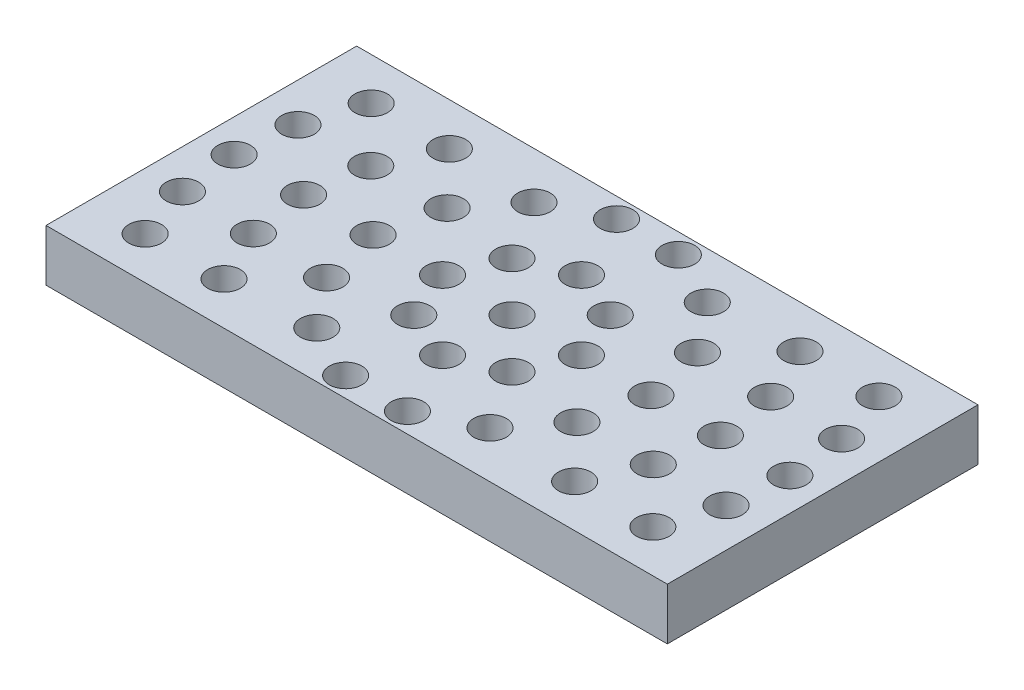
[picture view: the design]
ISO-10303-21;
HEADER;
FILE_DESCRIPTION(('STEP AP214'),'2;1');
FILE_NAME('part.step','',(''),(''),'','','');
FILE_SCHEMA(('AUTOMOTIVE_DESIGN { 1 0 10303 214 1 1 1 1 }'));
ENDSEC;
DATA;
#1=APPLICATION_CONTEXT('core data for automotive mechanical design processes');
#2=APPLICATION_PROTOCOL_DEFINITION('international standard','automotive_design',2000,#1);
#3=PRODUCT_CONTEXT('',#1,'mechanical');
#4=PRODUCT('Part','Part','',(#3));
#5=PRODUCT_RELATED_PRODUCT_CATEGORY('part','',(#4));
#6=PRODUCT_DEFINITION_FORMATION('','',#4);
#7=PRODUCT_DEFINITION_CONTEXT('part definition',#1,'design');
#8=PRODUCT_DEFINITION('design','',#6,#7);
#9=PRODUCT_DEFINITION_SHAPE('','',#8);
#10=(LENGTH_UNIT() NAMED_UNIT(*) SI_UNIT(.MILLI.,.METRE.));
#11=(NAMED_UNIT(*) PLANE_ANGLE_UNIT() SI_UNIT($,.RADIAN.));
#12=(NAMED_UNIT(*) SI_UNIT($,.STERADIAN.) SOLID_ANGLE_UNIT());
#13=UNCERTAINTY_MEASURE_WITH_UNIT(LENGTH_MEASURE(1.E-05),#10,'distance_accuracy_value','');
#14=(GEOMETRIC_REPRESENTATION_CONTEXT(3) GLOBAL_UNCERTAINTY_ASSIGNED_CONTEXT((#13)) GLOBAL_UNIT_ASSIGNED_CONTEXT((#10,
#11,#12)) REPRESENTATION_CONTEXT('',''));
#15=CARTESIAN_POINT('',(0.,0.,0.));
#16=DIRECTION('',(0.,0.,1.));
#17=DIRECTION('',(1.,0.,0.));
#18=AXIS2_PLACEMENT_3D('',#15,#16,#17);
#19=CARTESIAN_POINT('',(-76.2,12.7,-38.1));
#20=DIRECTION('',(1.,0.,0.));
#21=DIRECTION('',(0.,0.,-1.));
#22=AXIS2_PLACEMENT_3D('',#19,#20,#21);
#23=PLANE('',#22);
#24=DIRECTION('',(0.,0.,1.));
#25=VECTOR('',#24,1.);
#26=CARTESIAN_POINT('',(-76.2,0.,-38.1));
#27=LINE('',#26,#25);
#28=CARTESIAN_POINT('',(-76.2,0.,-38.1));
#29=VERTEX_POINT('',#28);
#30=CARTESIAN_POINT('',(-76.2,0.,38.1));
#31=VERTEX_POINT('',#30);
#32=EDGE_CURVE('E97',#29,#31,#27,.T.);
#33=ORIENTED_EDGE('',*,*,#32,.T.);
#34=DIRECTION('',(0.,-1.,0.));
#35=VECTOR('',#34,1.);
#36=CARTESIAN_POINT('',(-76.2,12.7,38.1));
#37=LINE('',#36,#35);
#38=CARTESIAN_POINT('',(-76.2,12.7,38.1));
#39=VERTEX_POINT('',#38);
#40=EDGE_CURVE('E12',#39,#31,#37,.T.);
#41=ORIENTED_EDGE('',*,*,#40,.F.);
#42=DIRECTION('',(0.,0.,1.));
#43=VECTOR('',#42,1.);
#44=CARTESIAN_POINT('',(-76.2,12.7,-38.1));
#45=LINE('',#44,#43);
#46=CARTESIAN_POINT('',(-76.2,12.7,-38.1));
#47=VERTEX_POINT('',#46);
#48=EDGE_CURVE('E85',#47,#39,#45,.T.);
#49=ORIENTED_EDGE('',*,*,#48,.F.);
#50=DIRECTION('',(0.,-1.,0.));
#51=VECTOR('',#50,1.);
#52=CARTESIAN_POINT('',(-76.2,12.7,-38.1));
#53=LINE('',#52,#51);
#54=EDGE_CURVE('E93',#47,#29,#53,.T.);
#55=ORIENTED_EDGE('',*,*,#54,.T.);
#56=EDGE_LOOP('',(#33,#41,#49,#55));
#57=FACE_BOUND('',#56,.T.);
#58=ADVANCED_FACE('F34',(#57),#23,.F.);
#59=CARTESIAN_POINT('',(-76.2,12.7,38.1));
#60=DIRECTION('',(0.,0.,-1.));
#61=DIRECTION('',(-1.,0.,0.));
#62=AXIS2_PLACEMENT_3D('',#59,#60,#61);
#63=PLANE('',#62);
#64=DIRECTION('',(1.,0.,0.));
#65=VECTOR('',#64,1.);
#66=CARTESIAN_POINT('',(-76.2,0.,38.1));
#67=LINE('',#66,#65);
#68=CARTESIAN_POINT('',(76.2,0.,38.1));
#69=VERTEX_POINT('',#68);
#70=EDGE_CURVE('E89',#31,#69,#67,.T.);
#71=ORIENTED_EDGE('',*,*,#70,.T.);
#72=DIRECTION('',(0.,-1.,0.));
#73=VECTOR('',#72,1.);
#74=CARTESIAN_POINT('',(76.2,12.7,38.1));
#75=LINE('',#74,#73);
#76=CARTESIAN_POINT('',(76.2,12.7,38.1));
#77=VERTEX_POINT('',#76);
#78=EDGE_CURVE('E42',#77,#69,#75,.T.);
#79=ORIENTED_EDGE('',*,*,#78,.F.);
#80=DIRECTION('',(1.,0.,0.));
#81=VECTOR('',#80,1.);
#82=CARTESIAN_POINT('',(-76.2,12.7,38.1));
#83=LINE('',#82,#81);
#84=EDGE_CURVE('E80',#39,#77,#83,.T.);
#85=ORIENTED_EDGE('',*,*,#84,.F.);
#86=ORIENTED_EDGE('',*,*,#40,.T.);
#87=EDGE_LOOP('',(#71,#79,#85,#86));
#88=FACE_BOUND('',#87,.T.);
#89=ADVANCED_FACE('F88',(#88),#63,.F.);
#90=CARTESIAN_POINT('',(76.2,12.7,-38.1));
#91=DIRECTION('',(-1.,0.,0.));
#92=DIRECTION('',(0.,0.,1.));
#93=AXIS2_PLACEMENT_3D('',#90,#91,#92);
#94=PLANE('',#93);
#95=DIRECTION('',(0.,0.,-1.));
#96=VECTOR('',#95,1.);
#97=CARTESIAN_POINT('',(76.2,0.,-38.1));
#98=LINE('',#97,#96);
#99=CARTESIAN_POINT('',(76.2,0.,-38.1));
#100=VERTEX_POINT('',#99);
#101=EDGE_CURVE('E67',#69,#100,#98,.T.);
#102=ORIENTED_EDGE('',*,*,#101,.T.);
#103=DIRECTION('',(0.,-1.,0.));
#104=VECTOR('',#103,1.);
#105=CARTESIAN_POINT('',(76.2,12.7,-38.1));
#106=LINE('',#105,#104);
#107=CARTESIAN_POINT('',(76.2,12.7,-38.1));
#108=VERTEX_POINT('',#107);
#109=EDGE_CURVE('E90',#108,#100,#106,.T.);
#110=ORIENTED_EDGE('',*,*,#109,.F.);
#111=DIRECTION('',(0.,0.,-1.));
#112=VECTOR('',#111,1.);
#113=CARTESIAN_POINT('',(76.2,12.7,-38.1));
#114=LINE('',#113,#112);
#115=EDGE_CURVE('E83',#77,#108,#114,.T.);
#116=ORIENTED_EDGE('',*,*,#115,.F.);
#117=ORIENTED_EDGE('',*,*,#78,.T.);
#118=EDGE_LOOP('',(#102,#110,#116,#117));
#119=FACE_BOUND('',#118,.T.);
#120=ADVANCED_FACE('F91',(#119),#94,.F.);
#121=CARTESIAN_POINT('',(-76.2,12.7,-38.1));
#122=DIRECTION('',(0.,0.,1.));
#123=DIRECTION('',(1.,0.,0.));
#124=AXIS2_PLACEMENT_3D('',#121,#122,#123);
#125=PLANE('',#124);
#126=DIRECTION('',(-1.,0.,0.));
#127=VECTOR('',#126,1.);
#128=CARTESIAN_POINT('',(-76.2,0.,-38.1));
#129=LINE('',#128,#127);
#130=EDGE_CURVE('E73',#100,#29,#129,.T.);
#131=ORIENTED_EDGE('',*,*,#130,.T.);
#132=ORIENTED_EDGE('',*,*,#54,.F.);
#133=DIRECTION('',(-1.,0.,0.));
#134=VECTOR('',#133,1.);
#135=CARTESIAN_POINT('',(-76.2,12.7,-38.1));
#136=LINE('',#135,#134);
#137=EDGE_CURVE('E50',#108,#47,#136,.T.);
#138=ORIENTED_EDGE('',*,*,#137,.F.);
#139=ORIENTED_EDGE('',*,*,#109,.T.);
#140=EDGE_LOOP('',(#131,#132,#138,#139));
#141=FACE_BOUND('',#140,.T.);
#142=ADVANCED_FACE('F105',(#141),#125,.F.);
#143=CARTESIAN_POINT('',(-76.2,12.7,38.1));
#144=DIRECTION('',(0.,1.,0.));
#145=DIRECTION('',(0.,0.,1.));
#146=AXIS2_PLACEMENT_3D('',#143,#144,#145);
#147=PLANE('',#146);
#148=CARTESIAN_POINT('',(66.6659939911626,12.7,-14.1702944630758));
#149=DIRECTION('',(0.,1.,0.));
#150=DIRECTION('',(1.,0.,0.));
#151=AXIS2_PLACEMENT_3D('',#148,#149,#150);
#152=CIRCLE('',#151,4.);
#153=CARTESIAN_POINT('',(70.6659939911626,12.7,-14.1702944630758));
#154=VERTEX_POINT('',#153);
#155=EDGE_CURVE('E363',#154,#154,#152,.T.);
#156=ORIENTED_EDGE('',*,*,#155,.F.);
#157=EDGE_LOOP('',(#156));
#158=FACE_BOUND('',#157,.T.);
#159=CARTESIAN_POINT('',(62.2630121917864,12.7,-27.7212790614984));
#160=DIRECTION('',(0.,1.,0.));
#161=DIRECTION('',(1.,0.,0.));
#162=AXIS2_PLACEMENT_3D('',#159,#160,#161);
#163=CIRCLE('',#162,4.);
#164=CARTESIAN_POINT('',(66.2630121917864,12.7,-27.7212790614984));
#165=VERTEX_POINT('',#164);
#166=EDGE_CURVE('E357',#165,#165,#163,.T.);
#167=ORIENTED_EDGE('',*,*,#166,.F.);
#168=EDGE_LOOP('',(#167));
#169=FACE_BOUND('',#168,.T.);
#170=CARTESIAN_POINT('',(49.0459359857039,12.7,-14.4011861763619));
#171=DIRECTION('',(0.,1.,0.));
#172=DIRECTION('',(1.,0.,0.));
#173=AXIS2_PLACEMENT_3D('',#170,#171,#172);
#174=CIRCLE('',#173,4.);
#175=CARTESIAN_POINT('',(53.0459359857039,12.7,-14.4011861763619));
#176=VERTEX_POINT('',#175);
#177=EDGE_CURVE('E351',#176,#176,#174,.T.);
#178=ORIENTED_EDGE('',*,*,#177,.F.);
#179=EDGE_LOOP('',(#178));
#180=FACE_BOUND('',#179,.T.);
#181=CARTESIAN_POINT('',(43.0019479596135,12.7,-27.6356738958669));
#182=DIRECTION('',(0.,1.,0.));
#183=DIRECTION('',(1.,0.,0.));
#184=AXIS2_PLACEMENT_3D('',#181,#182,#183);
#185=CIRCLE('',#184,4.);
#186=CARTESIAN_POINT('',(47.0019479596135,12.7,-27.6356738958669));
#187=VERTEX_POINT('',#186);
#188=EDGE_CURVE('E345',#187,#187,#185,.T.);
#189=ORIENTED_EDGE('',*,*,#188,.F.);
#190=EDGE_LOOP('',(#189));
#191=FACE_BOUND('',#190,.T.);
#192=CARTESIAN_POINT('',(-62.2630121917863,12.7,-27.7212790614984));
#193=DIRECTION('',(0.,1.,0.));
#194=DIRECTION('',(1.,0.,0.));
#195=AXIS2_PLACEMENT_3D('',#192,#193,#194);
#196=CIRCLE('',#195,4.);
#197=CARTESIAN_POINT('',(-58.2630121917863,12.7,-27.7212790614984));
#198=VERTEX_POINT('',#197);
#199=EDGE_CURVE('E339',#198,#198,#196,.T.);
#200=ORIENTED_EDGE('',*,*,#199,.F.);
#201=EDGE_LOOP('',(#200));
#202=FACE_BOUND('',#201,.T.);
#203=CARTESIAN_POINT('',(-66.6659939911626,12.7,-14.1702944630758));
#204=DIRECTION('',(0.,1.,0.));
#205=DIRECTION('',(1.,0.,0.));
#206=AXIS2_PLACEMENT_3D('',#203,#204,#205);
#207=CIRCLE('',#206,4.);
#208=CARTESIAN_POINT('',(-62.6659939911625,12.7,-14.1702944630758));
#209=VERTEX_POINT('',#208);
#210=EDGE_CURVE('E333',#209,#209,#207,.T.);
#211=ORIENTED_EDGE('',*,*,#210,.F.);
#212=EDGE_LOOP('',(#211));
#213=FACE_BOUND('',#212,.T.);
#214=CARTESIAN_POINT('',(-68.1553519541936,12.7,0.));
#215=DIRECTION('',(0.,1.,0.));
#216=DIRECTION('',(1.,0.,0.));
#217=AXIS2_PLACEMENT_3D('',#214,#215,#216);
#218=CIRCLE('',#217,4.);
#219=CARTESIAN_POINT('',(-64.1553519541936,12.7,0.));
#220=VERTEX_POINT('',#219);
#221=EDGE_CURVE('E327',#220,#220,#218,.T.);
#222=ORIENTED_EDGE('',*,*,#221,.F.);
#223=EDGE_LOOP('',(#222));
#224=FACE_BOUND('',#223,.T.);
#225=CARTESIAN_POINT('',(-66.6659939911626,12.7,14.1702944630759));
#226=DIRECTION('',(0.,1.,0.));
#227=DIRECTION('',(1.,0.,0.));
#228=AXIS2_PLACEMENT_3D('',#225,#226,#227);
#229=CIRCLE('',#228,4.);
#230=CARTESIAN_POINT('',(-62.6659939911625,12.7,14.1702944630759));
#231=VERTEX_POINT('',#230);
#232=EDGE_CURVE('E321',#231,#231,#229,.T.);
#233=ORIENTED_EDGE('',*,*,#232,.F.);
#234=EDGE_LOOP('',(#233));
#235=FACE_BOUND('',#234,.T.);
#236=CARTESIAN_POINT('',(-62.2630121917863,12.7,27.7212790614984));
#237=DIRECTION('',(0.,1.,0.));
#238=DIRECTION('',(1.,0.,0.));
#239=AXIS2_PLACEMENT_3D('',#236,#237,#238);
#240=CIRCLE('',#239,4.);
#241=CARTESIAN_POINT('',(-58.2630121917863,12.7,27.7212790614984));
#242=VERTEX_POINT('',#241);
#243=EDGE_CURVE('E315',#242,#242,#240,.T.);
#244=ORIENTED_EDGE('',*,*,#243,.F.);
#245=EDGE_LOOP('',(#244));
#246=FACE_BOUND('',#245,.T.);
#247=CARTESIAN_POINT('',(-43.0019479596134,12.7,-27.6356738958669));
#248=DIRECTION('',(0.,1.,0.));
#249=DIRECTION('',(1.,0.,0.));
#250=AXIS2_PLACEMENT_3D('',#247,#248,#249);
#251=CIRCLE('',#250,4.);
#252=CARTESIAN_POINT('',(-39.0019479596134,12.7,-27.6356738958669));
#253=VERTEX_POINT('',#252);
#254=EDGE_CURVE('E309',#253,#253,#251,.T.);
#255=ORIENTED_EDGE('',*,*,#254,.F.);
#256=EDGE_LOOP('',(#255));
#257=FACE_BOUND('',#256,.T.);
#258=CARTESIAN_POINT('',(30.7029251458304,12.7,-14.7857494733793));
#259=DIRECTION('',(0.,1.,0.));
#260=DIRECTION('',(1.,0.,0.));
#261=AXIS2_PLACEMENT_3D('',#258,#259,#260);
#262=CIRCLE('',#261,4.);
#263=CARTESIAN_POINT('',(34.7029251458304,12.7,-14.7857494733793));
#264=VERTEX_POINT('',#263);
#265=EDGE_CURVE('E303',#264,#264,#262,.T.);
#266=ORIENTED_EDGE('',*,*,#265,.F.);
#267=EDGE_LOOP('',(#266));
#268=FACE_BOUND('',#267,.T.);
#269=CARTESIAN_POINT('',(-49.0459359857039,12.7,-14.4011861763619));
#270=DIRECTION('',(0.,1.,0.));
#271=DIRECTION('',(1.,0.,0.));
#272=AXIS2_PLACEMENT_3D('',#269,#270,#271);
#273=CIRCLE('',#272,4.);
#274=CARTESIAN_POINT('',(-45.0459359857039,12.7,-14.4011861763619));
#275=VERTEX_POINT('',#274);
#276=EDGE_CURVE('E297',#275,#275,#273,.T.);
#277=ORIENTED_EDGE('',*,*,#276,.F.);
#278=EDGE_LOOP('',(#277));
#279=FACE_BOUND('',#278,.T.);
#280=CARTESIAN_POINT('',(21.2470834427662,12.7,-26.6429999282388));
#281=DIRECTION('',(0.,1.,0.));
#282=DIRECTION('',(1.,0.,0.));
#283=AXIS2_PLACEMENT_3D('',#280,#281,#282);
#284=CIRCLE('',#283,4.);
#285=CARTESIAN_POINT('',(25.2470834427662,12.7,-26.6429999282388));
#286=VERTEX_POINT('',#285);
#287=EDGE_CURVE('E291',#286,#286,#284,.T.);
#288=ORIENTED_EDGE('',*,*,#287,.F.);
#289=EDGE_LOOP('',(#288));
#290=FACE_BOUND('',#289,.T.);
#291=CARTESIAN_POINT('',(-51.1165139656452,12.7,0.));
#292=DIRECTION('',(0.,1.,0.));
#293=DIRECTION('',(1.,0.,0.));
#294=AXIS2_PLACEMENT_3D('',#291,#292,#293);
#295=CIRCLE('',#294,4.);
#296=CARTESIAN_POINT('',(-47.1165139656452,12.7,0.));
#297=VERTEX_POINT('',#296);
#298=EDGE_CURVE('E285',#297,#297,#295,.T.);
#299=ORIENTED_EDGE('',*,*,#298,.F.);
#300=EDGE_LOOP('',(#299));
#301=FACE_BOUND('',#300,.T.);
#302=CARTESIAN_POINT('',(7.58299628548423,12.7,-33.2232774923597));
#303=DIRECTION('',(0.,1.,0.));
#304=DIRECTION('',(1.,0.,0.));
#305=AXIS2_PLACEMENT_3D('',#302,#303,#304);
#306=CIRCLE('',#305,4.);
#307=CARTESIAN_POINT('',(11.5829962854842,12.7,-33.2232774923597));
#308=VERTEX_POINT('',#307);
#309=EDGE_CURVE('E279',#308,#308,#306,.T.);
#310=ORIENTED_EDGE('',*,*,#309,.F.);
#311=EDGE_LOOP('',(#310));
#312=FACE_BOUND('',#311,.T.);
#313=CARTESIAN_POINT('',(-49.0459359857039,12.7,14.4011861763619));
#314=DIRECTION('',(0.,1.,0.));
#315=DIRECTION('',(1.,0.,0.));
#316=AXIS2_PLACEMENT_3D('',#313,#314,#315);
#317=CIRCLE('',#316,4.);
#318=CARTESIAN_POINT('',(-45.0459359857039,12.7,14.4011861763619));
#319=VERTEX_POINT('',#318);
#320=EDGE_CURVE('E273',#319,#319,#317,.T.);
#321=ORIENTED_EDGE('',*,*,#320,.F.);
#322=EDGE_LOOP('',(#321));
#323=FACE_BOUND('',#322,.T.);
#324=CARTESIAN_POINT('',(-7.58299628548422,12.7,-33.2232774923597));
#325=DIRECTION('',(0.,1.,0.));
#326=DIRECTION('',(1.,0.,0.));
#327=AXIS2_PLACEMENT_3D('',#324,#325,#326);
#328=CIRCLE('',#327,4.);
#329=CARTESIAN_POINT('',(-3.58299628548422,12.7,-33.2232774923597));
#330=VERTEX_POINT('',#329);
#331=EDGE_CURVE('E267',#330,#330,#328,.T.);
#332=ORIENTED_EDGE('',*,*,#331,.F.);
#333=EDGE_LOOP('',(#332));
#334=FACE_BOUND('',#333,.T.);
#335=CARTESIAN_POINT('',(-43.0019479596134,12.7,27.6356738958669));
#336=DIRECTION('',(0.,1.,0.));
#337=DIRECTION('',(1.,0.,0.));
#338=AXIS2_PLACEMENT_3D('',#335,#336,#337);
#339=CIRCLE('',#338,4.);
#340=CARTESIAN_POINT('',(-39.0019479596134,12.7,27.6356738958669));
#341=VERTEX_POINT('',#340);
#342=EDGE_CURVE('E261',#341,#341,#339,.T.);
#343=ORIENTED_EDGE('',*,*,#342,.F.);
#344=EDGE_LOOP('',(#343));
#345=FACE_BOUND('',#344,.T.);
#346=CARTESIAN_POINT('',(-21.2470834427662,12.7,-26.6429999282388));
#347=DIRECTION('',(0.,1.,0.));
#348=DIRECTION('',(1.,0.,0.));
#349=AXIS2_PLACEMENT_3D('',#346,#347,#348);
#350=CIRCLE('',#349,4.);
#351=CARTESIAN_POINT('',(-17.2470834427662,12.7,-26.6429999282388));
#352=VERTEX_POINT('',#351);
#353=EDGE_CURVE('E255',#352,#352,#350,.T.);
#354=ORIENTED_EDGE('',*,*,#353,.F.);
#355=EDGE_LOOP('',(#354));
#356=FACE_BOUND('',#355,.T.);
#357=CARTESIAN_POINT('',(-30.7029251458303,12.7,-14.7857494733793));
#358=DIRECTION('',(0.,1.,0.));
#359=DIRECTION('',(1.,0.,0.));
#360=AXIS2_PLACEMENT_3D('',#357,#358,#359);
#361=CIRCLE('',#360,4.);
#362=CARTESIAN_POINT('',(-26.7029251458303,12.7,-14.7857494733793));
#363=VERTEX_POINT('',#362);
#364=EDGE_CURVE('E249',#363,#363,#361,.T.);
#365=ORIENTED_EDGE('',*,*,#364,.F.);
#366=EDGE_LOOP('',(#365));
#367=FACE_BOUND('',#366,.T.);
#368=CARTESIAN_POINT('',(-34.0776759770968,12.7,0.));
#369=DIRECTION('',(0.,1.,0.));
#370=DIRECTION('',(1.,0.,0.));
#371=AXIS2_PLACEMENT_3D('',#368,#369,#370);
#372=CIRCLE('',#371,4.);
#373=CARTESIAN_POINT('',(-30.0776759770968,12.7,0.));
#374=VERTEX_POINT('',#373);
#375=EDGE_CURVE('E243',#374,#374,#372,.T.);
#376=ORIENTED_EDGE('',*,*,#375,.F.);
#377=EDGE_LOOP('',(#376));
#378=FACE_BOUND('',#377,.T.);
#379=CARTESIAN_POINT('',(12.0482778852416,12.7,-12.0482778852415));
#380=DIRECTION('',(0.,1.,0.));
#381=DIRECTION('',(1.,0.,0.));
#382=AXIS2_PLACEMENT_3D('',#379,#380,#381);
#383=CIRCLE('',#382,4.);
#384=CARTESIAN_POINT('',(16.0482778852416,12.7,-12.0482778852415));
#385=VERTEX_POINT('',#384);
#386=EDGE_CURVE('E237',#385,#385,#383,.T.);
#387=ORIENTED_EDGE('',*,*,#386,.F.);
#388=EDGE_LOOP('',(#387));
#389=FACE_BOUND('',#388,.T.);
#390=CARTESIAN_POINT('',(-30.7029251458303,12.7,14.7857494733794));
#391=DIRECTION('',(0.,1.,0.));
#392=DIRECTION('',(1.,0.,0.));
#393=AXIS2_PLACEMENT_3D('',#390,#391,#392);
#394=CIRCLE('',#393,4.);
#395=CARTESIAN_POINT('',(-26.7029251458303,12.7,14.7857494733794));
#396=VERTEX_POINT('',#395);
#397=EDGE_CURVE('E231',#396,#396,#394,.T.);
#398=ORIENTED_EDGE('',*,*,#397,.F.);
#399=EDGE_LOOP('',(#398));
#400=FACE_BOUND('',#399,.T.);
#401=CARTESIAN_POINT('',(0.,12.7,-17.0388379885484));
#402=DIRECTION('',(0.,1.,0.));
#403=DIRECTION('',(1.,0.,0.));
#404=AXIS2_PLACEMENT_3D('',#401,#402,#403);
#405=CIRCLE('',#404,4.);
#406=CARTESIAN_POINT('',(4.00000000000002,12.7,-17.0388379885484));
#407=VERTEX_POINT('',#406);
#408=EDGE_CURVE('E225',#407,#407,#405,.T.);
#409=ORIENTED_EDGE('',*,*,#408,.F.);
#410=EDGE_LOOP('',(#409));
#411=FACE_BOUND('',#410,.T.);
#412=CARTESIAN_POINT('',(-21.2470834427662,12.7,26.6429999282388));
#413=DIRECTION('',(0.,1.,0.));
#414=DIRECTION('',(1.,0.,0.));
#415=AXIS2_PLACEMENT_3D('',#412,#413,#414);
#416=CIRCLE('',#415,4.);
#417=CARTESIAN_POINT('',(-17.2470834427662,12.7,26.6429999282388));
#418=VERTEX_POINT('',#417);
#419=EDGE_CURVE('E219',#418,#418,#416,.T.);
#420=ORIENTED_EDGE('',*,*,#419,.F.);
#421=EDGE_LOOP('',(#420));
#422=FACE_BOUND('',#421,.T.);
#423=CARTESIAN_POINT('',(-12.0482778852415,12.7,-12.0482778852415));
#424=DIRECTION('',(0.,1.,0.));
#425=DIRECTION('',(1.,0.,0.));
#426=AXIS2_PLACEMENT_3D('',#423,#424,#425);
#427=CIRCLE('',#426,4.);
#428=CARTESIAN_POINT('',(-8.0482778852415,12.7,-12.0482778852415));
#429=VERTEX_POINT('',#428);
#430=EDGE_CURVE('E213',#429,#429,#427,.T.);
#431=ORIENTED_EDGE('',*,*,#430,.F.);
#432=EDGE_LOOP('',(#431));
#433=FACE_BOUND('',#432,.T.);
#434=CARTESIAN_POINT('',(-7.58299628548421,12.7,33.2232774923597));
#435=DIRECTION('',(0.,1.,0.));
#436=DIRECTION('',(1.,0.,0.));
#437=AXIS2_PLACEMENT_3D('',#434,#435,#436);
#438=CIRCLE('',#437,4.);
#439=CARTESIAN_POINT('',(-3.58299628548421,12.7,33.2232774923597));
#440=VERTEX_POINT('',#439);
#441=EDGE_CURVE('E207',#440,#440,#438,.T.);
#442=ORIENTED_EDGE('',*,*,#441,.F.);
#443=EDGE_LOOP('',(#442));
#444=FACE_BOUND('',#443,.T.);
#445=CARTESIAN_POINT('',(-17.0388379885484,12.7,0.));
#446=DIRECTION('',(0.,1.,0.));
#447=DIRECTION('',(1.,0.,0.));
#448=AXIS2_PLACEMENT_3D('',#445,#446,#447);
#449=CIRCLE('',#448,4.);
#450=CARTESIAN_POINT('',(-13.0388379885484,12.7,0.));
#451=VERTEX_POINT('',#450);
#452=EDGE_CURVE('E201',#451,#451,#449,.T.);
#453=ORIENTED_EDGE('',*,*,#452,.F.);
#454=EDGE_LOOP('',(#453));
#455=FACE_BOUND('',#454,.T.);
#456=CARTESIAN_POINT('',(7.58299628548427,12.7,33.2232774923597));
#457=DIRECTION('',(0.,1.,0.));
#458=DIRECTION('',(1.,0.,0.));
#459=AXIS2_PLACEMENT_3D('',#456,#457,#458);
#460=CIRCLE('',#459,4.);
#461=CARTESIAN_POINT('',(11.5829962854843,12.7,33.2232774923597));
#462=VERTEX_POINT('',#461);
#463=EDGE_CURVE('E195',#462,#462,#460,.T.);
#464=ORIENTED_EDGE('',*,*,#463,.F.);
#465=EDGE_LOOP('',(#464));
#466=FACE_BOUND('',#465,.T.);
#467=CARTESIAN_POINT('',(-12.0482778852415,12.7,12.0482778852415));
#468=DIRECTION('',(0.,1.,0.));
#469=DIRECTION('',(1.,0.,0.));
#470=AXIS2_PLACEMENT_3D('',#467,#468,#469);
#471=CIRCLE('',#470,4.);
#472=CARTESIAN_POINT('',(-8.0482778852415,12.7,12.0482778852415));
#473=VERTEX_POINT('',#472);
#474=EDGE_CURVE('E189',#473,#473,#471,.T.);
#475=ORIENTED_EDGE('',*,*,#474,.F.);
#476=EDGE_LOOP('',(#475));
#477=FACE_BOUND('',#476,.T.);
#478=CARTESIAN_POINT('',(62.2630121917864,12.7,27.7212790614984));
#479=DIRECTION('',(0.,1.,0.));
#480=DIRECTION('',(1.,0.,0.));
#481=AXIS2_PLACEMENT_3D('',#478,#479,#480);
#482=CIRCLE('',#481,4.);
#483=CARTESIAN_POINT('',(66.2630121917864,12.7,27.7212790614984));
#484=VERTEX_POINT('',#483);
#485=EDGE_CURVE('E183',#484,#484,#482,.T.);
#486=ORIENTED_EDGE('',*,*,#485,.F.);
#487=EDGE_LOOP('',(#486));
#488=FACE_BOUND('',#487,.T.);
#489=CARTESIAN_POINT('',(43.0019479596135,12.7,27.6356738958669));
#490=DIRECTION('',(0.,1.,0.));
#491=DIRECTION('',(1.,0.,0.));
#492=AXIS2_PLACEMENT_3D('',#489,#490,#491);
#493=CIRCLE('',#492,4.);
#494=CARTESIAN_POINT('',(47.0019479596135,12.7,27.6356738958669));
#495=VERTEX_POINT('',#494);
#496=EDGE_CURVE('E177',#495,#495,#493,.T.);
#497=ORIENTED_EDGE('',*,*,#496,.F.);
#498=EDGE_LOOP('',(#497));
#499=FACE_BOUND('',#498,.T.);
#500=CARTESIAN_POINT('',(21.2470834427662,12.7,26.6429999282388));
#501=DIRECTION('',(0.,1.,0.));
#502=DIRECTION('',(1.,0.,0.));
#503=AXIS2_PLACEMENT_3D('',#500,#501,#502);
#504=CIRCLE('',#503,4.);
#505=CARTESIAN_POINT('',(25.2470834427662,12.7,26.6429999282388));
#506=VERTEX_POINT('',#505);
#507=EDGE_CURVE('E171',#506,#506,#504,.T.);
#508=ORIENTED_EDGE('',*,*,#507,.F.);
#509=EDGE_LOOP('',(#508));
#510=FACE_BOUND('',#509,.T.);
#511=CARTESIAN_POINT('',(0.,12.7,17.0388379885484));
#512=DIRECTION('',(0.,1.,0.));
#513=DIRECTION('',(1.,0.,0.));
#514=AXIS2_PLACEMENT_3D('',#511,#512,#513);
#515=CIRCLE('',#514,4.);
#516=CARTESIAN_POINT('',(4.00000000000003,12.7,17.0388379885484));
#517=VERTEX_POINT('',#516);
#518=EDGE_CURVE('E165',#517,#517,#515,.T.);
#519=ORIENTED_EDGE('',*,*,#518,.F.);
#520=EDGE_LOOP('',(#519));
#521=FACE_BOUND('',#520,.T.);
#522=CARTESIAN_POINT('',(66.6659939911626,12.7,14.1702944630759));
#523=DIRECTION('',(0.,1.,0.));
#524=DIRECTION('',(1.,0.,0.));
#525=AXIS2_PLACEMENT_3D('',#522,#523,#524);
#526=CIRCLE('',#525,4.);
#527=CARTESIAN_POINT('',(70.6659939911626,12.7,14.1702944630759));
#528=VERTEX_POINT('',#527);
#529=EDGE_CURVE('E159',#528,#528,#526,.T.);
#530=ORIENTED_EDGE('',*,*,#529,.F.);
#531=EDGE_LOOP('',(#530));
#532=FACE_BOUND('',#531,.T.);
#533=CARTESIAN_POINT('',(49.0459359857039,12.7,14.4011861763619));
#534=DIRECTION('',(0.,1.,0.));
#535=DIRECTION('',(1.,0.,0.));
#536=AXIS2_PLACEMENT_3D('',#533,#534,#535);
#537=CIRCLE('',#536,4.);
#538=CARTESIAN_POINT('',(53.0459359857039,12.7,14.4011861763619));
#539=VERTEX_POINT('',#538);
#540=EDGE_CURVE('E153',#539,#539,#537,.T.);
#541=ORIENTED_EDGE('',*,*,#540,.F.);
#542=EDGE_LOOP('',(#541));
#543=FACE_BOUND('',#542,.T.);
#544=CARTESIAN_POINT('',(30.7029251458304,12.7,14.7857494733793));
#545=DIRECTION('',(0.,1.,0.));
#546=DIRECTION('',(1.,0.,0.));
#547=AXIS2_PLACEMENT_3D('',#544,#545,#546);
#548=CIRCLE('',#547,4.);
#549=CARTESIAN_POINT('',(34.7029251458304,12.7,14.7857494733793));
#550=VERTEX_POINT('',#549);
#551=EDGE_CURVE('E147',#550,#550,#548,.T.);
#552=ORIENTED_EDGE('',*,*,#551,.F.);
#553=EDGE_LOOP('',(#552));
#554=FACE_BOUND('',#553,.T.);
#555=CARTESIAN_POINT('',(12.0482778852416,12.7,12.0482778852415));
#556=DIRECTION('',(0.,1.,0.));
#557=DIRECTION('',(1.,0.,0.));
#558=AXIS2_PLACEMENT_3D('',#555,#556,#557);
#559=CIRCLE('',#558,4.);
#560=CARTESIAN_POINT('',(16.0482778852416,12.7,12.0482778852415));
#561=VERTEX_POINT('',#560);
#562=EDGE_CURVE('E141',#561,#561,#559,.T.);
#563=ORIENTED_EDGE('',*,*,#562,.F.);
#564=EDGE_LOOP('',(#563));
#565=FACE_BOUND('',#564,.T.);
#566=CARTESIAN_POINT('',(68.1553519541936,12.7,0.));
#567=DIRECTION('',(0.,1.,0.));
#568=DIRECTION('',(1.,0.,0.));
#569=AXIS2_PLACEMENT_3D('',#566,#567,#568);
#570=CIRCLE('',#569,4.);
#571=CARTESIAN_POINT('',(72.1553519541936,12.7,0.));
#572=VERTEX_POINT('',#571);
#573=EDGE_CURVE('E135',#572,#572,#570,.T.);
#574=ORIENTED_EDGE('',*,*,#573,.F.);
#575=EDGE_LOOP('',(#574));
#576=FACE_BOUND('',#575,.T.);
#577=CARTESIAN_POINT('',(51.1165139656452,12.7,0.));
#578=DIRECTION('',(0.,1.,0.));
#579=DIRECTION('',(1.,0.,0.));
#580=AXIS2_PLACEMENT_3D('',#577,#578,#579);
#581=CIRCLE('',#580,4.);
#582=CARTESIAN_POINT('',(55.1165139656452,12.7,0.));
#583=VERTEX_POINT('',#582);
#584=EDGE_CURVE('E129',#583,#583,#581,.T.);
#585=ORIENTED_EDGE('',*,*,#584,.F.);
#586=EDGE_LOOP('',(#585));
#587=FACE_BOUND('',#586,.T.);
#588=CARTESIAN_POINT('',(34.0776759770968,12.7,0.));
#589=DIRECTION('',(0.,1.,0.));
#590=DIRECTION('',(1.,0.,0.));
#591=AXIS2_PLACEMENT_3D('',#588,#589,#590);
#592=CIRCLE('',#591,4.);
#593=CARTESIAN_POINT('',(38.0776759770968,12.7,0.));
#594=VERTEX_POINT('',#593);
#595=EDGE_CURVE('E123',#594,#594,#592,.T.);
#596=ORIENTED_EDGE('',*,*,#595,.F.);
#597=EDGE_LOOP('',(#596));
#598=FACE_BOUND('',#597,.T.);
#599=CARTESIAN_POINT('',(17.0388379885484,12.7,0.));
#600=DIRECTION('',(0.,1.,0.));
#601=DIRECTION('',(1.,0.,0.));
#602=AXIS2_PLACEMENT_3D('',#599,#600,#601);
#603=CIRCLE('',#602,4.);
#604=CARTESIAN_POINT('',(21.0388379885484,12.7,0.));
#605=VERTEX_POINT('',#604);
#606=EDGE_CURVE('E117',#605,#605,#603,.T.);
#607=ORIENTED_EDGE('',*,*,#606,.F.);
#608=EDGE_LOOP('',(#607));
#609=FACE_BOUND('',#608,.T.);
#610=CARTESIAN_POINT('',(0.,12.7,0.));
#611=DIRECTION('',(0.,1.,0.));
#612=DIRECTION('',(1.,0.,0.));
#613=AXIS2_PLACEMENT_3D('',#610,#611,#612);
#614=CIRCLE('',#613,4.);
#615=CARTESIAN_POINT('',(4.00000000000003,12.7,0.));
#616=VERTEX_POINT('',#615);
#617=EDGE_CURVE('E111',#616,#616,#614,.T.);
#618=ORIENTED_EDGE('',*,*,#617,.F.);
#619=EDGE_LOOP('',(#618));
#620=FACE_BOUND('',#619,.T.);
#621=ORIENTED_EDGE('',*,*,#48,.T.);
#622=ORIENTED_EDGE('',*,*,#84,.T.);
#623=ORIENTED_EDGE('',*,*,#115,.T.);
#624=ORIENTED_EDGE('',*,*,#137,.T.);
#625=EDGE_LOOP('',(#621,#622,#623,#624));
#626=FACE_BOUND('',#625,.T.);
#627=ADVANCED_FACE('F81',(#158,#169,#180,#191,#202,#213,#224,#235,#246,#257,#268,#279,#290,#301,
#312,#323,#334,#345,#356,#367,#378,#389,#400,#411,#422,#433,#444,#455,#466,#477,#488,#499,#510,
#521,#532,#543,#554,#565,#576,#587,#598,#609,#620,#626),#147,.T.);
#628=CARTESIAN_POINT('',(-76.2,0.,38.1));
#629=DIRECTION('',(0.,1.,0.));
#630=DIRECTION('',(0.,0.,1.));
#631=AXIS2_PLACEMENT_3D('',#628,#629,#630);
#632=PLANE('',#631);
#633=CARTESIAN_POINT('',(66.6659939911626,0.,-14.1702944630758));
#634=DIRECTION('',(0.,1.,0.));
#635=DIRECTION('',(1.,0.,0.));
#636=AXIS2_PLACEMENT_3D('',#633,#634,#635);
#637=CIRCLE('',#636,4.);
#638=CARTESIAN_POINT('',(70.6659939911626,0.,-14.1702944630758));
#639=VERTEX_POINT('',#638);
#640=EDGE_CURVE('E360',#639,#639,#637,.T.);
#641=ORIENTED_EDGE('',*,*,#640,.T.);
#642=EDGE_LOOP('',(#641));
#643=FACE_BOUND('',#642,.T.);
#644=CARTESIAN_POINT('',(62.2630121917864,0.,-27.7212790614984));
#645=DIRECTION('',(0.,1.,0.));
#646=DIRECTION('',(1.,0.,0.));
#647=AXIS2_PLACEMENT_3D('',#644,#645,#646);
#648=CIRCLE('',#647,4.);
#649=CARTESIAN_POINT('',(66.2630121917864,0.,-27.7212790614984));
#650=VERTEX_POINT('',#649);
#651=EDGE_CURVE('E354',#650,#650,#648,.T.);
#652=ORIENTED_EDGE('',*,*,#651,.T.);
#653=EDGE_LOOP('',(#652));
#654=FACE_BOUND('',#653,.T.);
#655=CARTESIAN_POINT('',(49.0459359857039,0.,-14.4011861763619));
#656=DIRECTION('',(0.,1.,0.));
#657=DIRECTION('',(1.,0.,0.));
#658=AXIS2_PLACEMENT_3D('',#655,#656,#657);
#659=CIRCLE('',#658,4.);
#660=CARTESIAN_POINT('',(53.0459359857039,0.,-14.4011861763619));
#661=VERTEX_POINT('',#660);
#662=EDGE_CURVE('E348',#661,#661,#659,.T.);
#663=ORIENTED_EDGE('',*,*,#662,.T.);
#664=EDGE_LOOP('',(#663));
#665=FACE_BOUND('',#664,.T.);
#666=CARTESIAN_POINT('',(43.0019479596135,0.,-27.6356738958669));
#667=DIRECTION('',(0.,1.,0.));
#668=DIRECTION('',(1.,0.,0.));
#669=AXIS2_PLACEMENT_3D('',#666,#667,#668);
#670=CIRCLE('',#669,4.);
#671=CARTESIAN_POINT('',(47.0019479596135,0.,-27.6356738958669));
#672=VERTEX_POINT('',#671);
#673=EDGE_CURVE('E342',#672,#672,#670,.T.);
#674=ORIENTED_EDGE('',*,*,#673,.T.);
#675=EDGE_LOOP('',(#674));
#676=FACE_BOUND('',#675,.T.);
#677=CARTESIAN_POINT('',(-62.2630121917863,0.,-27.7212790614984));
#678=DIRECTION('',(0.,1.,0.));
#679=DIRECTION('',(1.,0.,0.));
#680=AXIS2_PLACEMENT_3D('',#677,#678,#679);
#681=CIRCLE('',#680,4.);
#682=CARTESIAN_POINT('',(-58.2630121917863,0.,-27.7212790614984));
#683=VERTEX_POINT('',#682);
#684=EDGE_CURVE('E336',#683,#683,#681,.T.);
#685=ORIENTED_EDGE('',*,*,#684,.T.);
#686=EDGE_LOOP('',(#685));
#687=FACE_BOUND('',#686,.T.);
#688=CARTESIAN_POINT('',(-66.6659939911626,0.,-14.1702944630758));
#689=DIRECTION('',(0.,1.,0.));
#690=DIRECTION('',(1.,0.,0.));
#691=AXIS2_PLACEMENT_3D('',#688,#689,#690);
#692=CIRCLE('',#691,4.);
#693=CARTESIAN_POINT('',(-62.6659939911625,0.,-14.1702944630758));
#694=VERTEX_POINT('',#693);
#695=EDGE_CURVE('E330',#694,#694,#692,.T.);
#696=ORIENTED_EDGE('',*,*,#695,.T.);
#697=EDGE_LOOP('',(#696));
#698=FACE_BOUND('',#697,.T.);
#699=CARTESIAN_POINT('',(-68.1553519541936,0.,0.));
#700=DIRECTION('',(0.,1.,0.));
#701=DIRECTION('',(1.,0.,0.));
#702=AXIS2_PLACEMENT_3D('',#699,#700,#701);
#703=CIRCLE('',#702,4.);
#704=CARTESIAN_POINT('',(-64.1553519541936,0.,0.));
#705=VERTEX_POINT('',#704);
#706=EDGE_CURVE('E324',#705,#705,#703,.T.);
#707=ORIENTED_EDGE('',*,*,#706,.T.);
#708=EDGE_LOOP('',(#707));
#709=FACE_BOUND('',#708,.T.);
#710=CARTESIAN_POINT('',(-66.6659939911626,0.,14.1702944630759));
#711=DIRECTION('',(0.,1.,0.));
#712=DIRECTION('',(1.,0.,0.));
#713=AXIS2_PLACEMENT_3D('',#710,#711,#712);
#714=CIRCLE('',#713,4.);
#715=CARTESIAN_POINT('',(-62.6659939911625,0.,14.1702944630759));
#716=VERTEX_POINT('',#715);
#717=EDGE_CURVE('E318',#716,#716,#714,.T.);
#718=ORIENTED_EDGE('',*,*,#717,.T.);
#719=EDGE_LOOP('',(#718));
#720=FACE_BOUND('',#719,.T.);
#721=CARTESIAN_POINT('',(-62.2630121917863,0.,27.7212790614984));
#722=DIRECTION('',(0.,1.,0.));
#723=DIRECTION('',(1.,0.,0.));
#724=AXIS2_PLACEMENT_3D('',#721,#722,#723);
#725=CIRCLE('',#724,4.);
#726=CARTESIAN_POINT('',(-58.2630121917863,0.,27.7212790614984));
#727=VERTEX_POINT('',#726);
#728=EDGE_CURVE('E312',#727,#727,#725,.T.);
#729=ORIENTED_EDGE('',*,*,#728,.T.);
#730=EDGE_LOOP('',(#729));
#731=FACE_BOUND('',#730,.T.);
#732=CARTESIAN_POINT('',(-43.0019479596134,0.,-27.6356738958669));
#733=DIRECTION('',(0.,1.,0.));
#734=DIRECTION('',(1.,0.,0.));
#735=AXIS2_PLACEMENT_3D('',#732,#733,#734);
#736=CIRCLE('',#735,4.);
#737=CARTESIAN_POINT('',(-39.0019479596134,0.,-27.6356738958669));
#738=VERTEX_POINT('',#737);
#739=EDGE_CURVE('E306',#738,#738,#736,.T.);
#740=ORIENTED_EDGE('',*,*,#739,.T.);
#741=EDGE_LOOP('',(#740));
#742=FACE_BOUND('',#741,.T.);
#743=CARTESIAN_POINT('',(30.7029251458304,0.,-14.7857494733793));
#744=DIRECTION('',(0.,1.,0.));
#745=DIRECTION('',(1.,0.,0.));
#746=AXIS2_PLACEMENT_3D('',#743,#744,#745);
#747=CIRCLE('',#746,4.);
#748=CARTESIAN_POINT('',(34.7029251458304,0.,-14.7857494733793));
#749=VERTEX_POINT('',#748);
#750=EDGE_CURVE('E300',#749,#749,#747,.T.);
#751=ORIENTED_EDGE('',*,*,#750,.T.);
#752=EDGE_LOOP('',(#751));
#753=FACE_BOUND('',#752,.T.);
#754=CARTESIAN_POINT('',(-49.0459359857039,0.,-14.4011861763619));
#755=DIRECTION('',(0.,1.,0.));
#756=DIRECTION('',(1.,0.,0.));
#757=AXIS2_PLACEMENT_3D('',#754,#755,#756);
#758=CIRCLE('',#757,4.);
#759=CARTESIAN_POINT('',(-45.0459359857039,0.,-14.4011861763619));
#760=VERTEX_POINT('',#759);
#761=EDGE_CURVE('E294',#760,#760,#758,.T.);
#762=ORIENTED_EDGE('',*,*,#761,.T.);
#763=EDGE_LOOP('',(#762));
#764=FACE_BOUND('',#763,.T.);
#765=CARTESIAN_POINT('',(21.2470834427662,0.,-26.6429999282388));
#766=DIRECTION('',(0.,1.,0.));
#767=DIRECTION('',(1.,0.,0.));
#768=AXIS2_PLACEMENT_3D('',#765,#766,#767);
#769=CIRCLE('',#768,4.);
#770=CARTESIAN_POINT('',(25.2470834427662,0.,-26.6429999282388));
#771=VERTEX_POINT('',#770);
#772=EDGE_CURVE('E288',#771,#771,#769,.T.);
#773=ORIENTED_EDGE('',*,*,#772,.T.);
#774=EDGE_LOOP('',(#773));
#775=FACE_BOUND('',#774,.T.);
#776=CARTESIAN_POINT('',(-51.1165139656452,0.,0.));
#777=DIRECTION('',(0.,1.,0.));
#778=DIRECTION('',(1.,0.,0.));
#779=AXIS2_PLACEMENT_3D('',#776,#777,#778);
#780=CIRCLE('',#779,4.);
#781=CARTESIAN_POINT('',(-47.1165139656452,0.,0.));
#782=VERTEX_POINT('',#781);
#783=EDGE_CURVE('E282',#782,#782,#780,.T.);
#784=ORIENTED_EDGE('',*,*,#783,.T.);
#785=EDGE_LOOP('',(#784));
#786=FACE_BOUND('',#785,.T.);
#787=CARTESIAN_POINT('',(7.58299628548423,0.,-33.2232774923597));
#788=DIRECTION('',(0.,1.,0.));
#789=DIRECTION('',(1.,0.,0.));
#790=AXIS2_PLACEMENT_3D('',#787,#788,#789);
#791=CIRCLE('',#790,4.);
#792=CARTESIAN_POINT('',(11.5829962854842,0.,-33.2232774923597));
#793=VERTEX_POINT('',#792);
#794=EDGE_CURVE('E276',#793,#793,#791,.T.);
#795=ORIENTED_EDGE('',*,*,#794,.T.);
#796=EDGE_LOOP('',(#795));
#797=FACE_BOUND('',#796,.T.);
#798=CARTESIAN_POINT('',(-49.0459359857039,0.,14.4011861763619));
#799=DIRECTION('',(0.,1.,0.));
#800=DIRECTION('',(1.,0.,0.));
#801=AXIS2_PLACEMENT_3D('',#798,#799,#800);
#802=CIRCLE('',#801,4.);
#803=CARTESIAN_POINT('',(-45.0459359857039,0.,14.4011861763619));
#804=VERTEX_POINT('',#803);
#805=EDGE_CURVE('E270',#804,#804,#802,.T.);
#806=ORIENTED_EDGE('',*,*,#805,.T.);
#807=EDGE_LOOP('',(#806));
#808=FACE_BOUND('',#807,.T.);
#809=CARTESIAN_POINT('',(-7.58299628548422,0.,-33.2232774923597));
#810=DIRECTION('',(0.,1.,0.));
#811=DIRECTION('',(1.,0.,0.));
#812=AXIS2_PLACEMENT_3D('',#809,#810,#811);
#813=CIRCLE('',#812,4.);
#814=CARTESIAN_POINT('',(-3.58299628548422,0.,-33.2232774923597));
#815=VERTEX_POINT('',#814);
#816=EDGE_CURVE('E264',#815,#815,#813,.T.);
#817=ORIENTED_EDGE('',*,*,#816,.T.);
#818=EDGE_LOOP('',(#817));
#819=FACE_BOUND('',#818,.T.);
#820=CARTESIAN_POINT('',(-43.0019479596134,0.,27.6356738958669));
#821=DIRECTION('',(0.,1.,0.));
#822=DIRECTION('',(1.,0.,0.));
#823=AXIS2_PLACEMENT_3D('',#820,#821,#822);
#824=CIRCLE('',#823,4.);
#825=CARTESIAN_POINT('',(-39.0019479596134,0.,27.6356738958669));
#826=VERTEX_POINT('',#825);
#827=EDGE_CURVE('E258',#826,#826,#824,.T.);
#828=ORIENTED_EDGE('',*,*,#827,.T.);
#829=EDGE_LOOP('',(#828));
#830=FACE_BOUND('',#829,.T.);
#831=CARTESIAN_POINT('',(-21.2470834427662,0.,-26.6429999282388));
#832=DIRECTION('',(0.,1.,0.));
#833=DIRECTION('',(1.,0.,0.));
#834=AXIS2_PLACEMENT_3D('',#831,#832,#833);
#835=CIRCLE('',#834,4.);
#836=CARTESIAN_POINT('',(-17.2470834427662,0.,-26.6429999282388));
#837=VERTEX_POINT('',#836);
#838=EDGE_CURVE('E252',#837,#837,#835,.T.);
#839=ORIENTED_EDGE('',*,*,#838,.T.);
#840=EDGE_LOOP('',(#839));
#841=FACE_BOUND('',#840,.T.);
#842=CARTESIAN_POINT('',(-30.7029251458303,0.,-14.7857494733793));
#843=DIRECTION('',(0.,1.,0.));
#844=DIRECTION('',(1.,0.,0.));
#845=AXIS2_PLACEMENT_3D('',#842,#843,#844);
#846=CIRCLE('',#845,4.);
#847=CARTESIAN_POINT('',(-26.7029251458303,0.,-14.7857494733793));
#848=VERTEX_POINT('',#847);
#849=EDGE_CURVE('E246',#848,#848,#846,.T.);
#850=ORIENTED_EDGE('',*,*,#849,.T.);
#851=EDGE_LOOP('',(#850));
#852=FACE_BOUND('',#851,.T.);
#853=CARTESIAN_POINT('',(-34.0776759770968,0.,0.));
#854=DIRECTION('',(0.,1.,0.));
#855=DIRECTION('',(1.,0.,0.));
#856=AXIS2_PLACEMENT_3D('',#853,#854,#855);
#857=CIRCLE('',#856,4.);
#858=CARTESIAN_POINT('',(-30.0776759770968,0.,0.));
#859=VERTEX_POINT('',#858);
#860=EDGE_CURVE('E240',#859,#859,#857,.T.);
#861=ORIENTED_EDGE('',*,*,#860,.T.);
#862=EDGE_LOOP('',(#861));
#863=FACE_BOUND('',#862,.T.);
#864=CARTESIAN_POINT('',(12.0482778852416,0.,-12.0482778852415));
#865=DIRECTION('',(0.,1.,0.));
#866=DIRECTION('',(1.,0.,0.));
#867=AXIS2_PLACEMENT_3D('',#864,#865,#866);
#868=CIRCLE('',#867,4.);
#869=CARTESIAN_POINT('',(16.0482778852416,0.,-12.0482778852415));
#870=VERTEX_POINT('',#869);
#871=EDGE_CURVE('E234',#870,#870,#868,.T.);
#872=ORIENTED_EDGE('',*,*,#871,.T.);
#873=EDGE_LOOP('',(#872));
#874=FACE_BOUND('',#873,.T.);
#875=CARTESIAN_POINT('',(-30.7029251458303,0.,14.7857494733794));
#876=DIRECTION('',(0.,1.,0.));
#877=DIRECTION('',(1.,0.,0.));
#878=AXIS2_PLACEMENT_3D('',#875,#876,#877);
#879=CIRCLE('',#878,4.);
#880=CARTESIAN_POINT('',(-26.7029251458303,0.,14.7857494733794));
#881=VERTEX_POINT('',#880);
#882=EDGE_CURVE('E228',#881,#881,#879,.T.);
#883=ORIENTED_EDGE('',*,*,#882,.T.);
#884=EDGE_LOOP('',(#883));
#885=FACE_BOUND('',#884,.T.);
#886=CARTESIAN_POINT('',(0.,0.,-17.0388379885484));
#887=DIRECTION('',(0.,1.,0.));
#888=DIRECTION('',(1.,0.,0.));
#889=AXIS2_PLACEMENT_3D('',#886,#887,#888);
#890=CIRCLE('',#889,4.);
#891=CARTESIAN_POINT('',(4.00000000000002,0.,-17.0388379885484));
#892=VERTEX_POINT('',#891);
#893=EDGE_CURVE('E222',#892,#892,#890,.T.);
#894=ORIENTED_EDGE('',*,*,#893,.T.);
#895=EDGE_LOOP('',(#894));
#896=FACE_BOUND('',#895,.T.);
#897=CARTESIAN_POINT('',(-21.2470834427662,0.,26.6429999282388));
#898=DIRECTION('',(0.,1.,0.));
#899=DIRECTION('',(1.,0.,0.));
#900=AXIS2_PLACEMENT_3D('',#897,#898,#899);
#901=CIRCLE('',#900,4.);
#902=CARTESIAN_POINT('',(-17.2470834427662,0.,26.6429999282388));
#903=VERTEX_POINT('',#902);
#904=EDGE_CURVE('E216',#903,#903,#901,.T.);
#905=ORIENTED_EDGE('',*,*,#904,.T.);
#906=EDGE_LOOP('',(#905));
#907=FACE_BOUND('',#906,.T.);
#908=CARTESIAN_POINT('',(-12.0482778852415,0.,-12.0482778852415));
#909=DIRECTION('',(0.,1.,0.));
#910=DIRECTION('',(1.,0.,0.));
#911=AXIS2_PLACEMENT_3D('',#908,#909,#910);
#912=CIRCLE('',#911,4.);
#913=CARTESIAN_POINT('',(-8.0482778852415,0.,-12.0482778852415));
#914=VERTEX_POINT('',#913);
#915=EDGE_CURVE('E210',#914,#914,#912,.T.);
#916=ORIENTED_EDGE('',*,*,#915,.T.);
#917=EDGE_LOOP('',(#916));
#918=FACE_BOUND('',#917,.T.);
#919=CARTESIAN_POINT('',(-7.58299628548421,0.,33.2232774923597));
#920=DIRECTION('',(0.,1.,0.));
#921=DIRECTION('',(1.,0.,0.));
#922=AXIS2_PLACEMENT_3D('',#919,#920,#921);
#923=CIRCLE('',#922,4.);
#924=CARTESIAN_POINT('',(-3.58299628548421,0.,33.2232774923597));
#925=VERTEX_POINT('',#924);
#926=EDGE_CURVE('E204',#925,#925,#923,.T.);
#927=ORIENTED_EDGE('',*,*,#926,.T.);
#928=EDGE_LOOP('',(#927));
#929=FACE_BOUND('',#928,.T.);
#930=CARTESIAN_POINT('',(-17.0388379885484,0.,0.));
#931=DIRECTION('',(0.,1.,0.));
#932=DIRECTION('',(1.,0.,0.));
#933=AXIS2_PLACEMENT_3D('',#930,#931,#932);
#934=CIRCLE('',#933,4.);
#935=CARTESIAN_POINT('',(-13.0388379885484,0.,0.));
#936=VERTEX_POINT('',#935);
#937=EDGE_CURVE('E198',#936,#936,#934,.T.);
#938=ORIENTED_EDGE('',*,*,#937,.T.);
#939=EDGE_LOOP('',(#938));
#940=FACE_BOUND('',#939,.T.);
#941=CARTESIAN_POINT('',(7.58299628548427,0.,33.2232774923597));
#942=DIRECTION('',(0.,1.,0.));
#943=DIRECTION('',(1.,0.,0.));
#944=AXIS2_PLACEMENT_3D('',#941,#942,#943);
#945=CIRCLE('',#944,4.);
#946=CARTESIAN_POINT('',(11.5829962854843,0.,33.2232774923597));
#947=VERTEX_POINT('',#946);
#948=EDGE_CURVE('E192',#947,#947,#945,.T.);
#949=ORIENTED_EDGE('',*,*,#948,.T.);
#950=EDGE_LOOP('',(#949));
#951=FACE_BOUND('',#950,.T.);
#952=CARTESIAN_POINT('',(-12.0482778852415,0.,12.0482778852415));
#953=DIRECTION('',(0.,1.,0.));
#954=DIRECTION('',(1.,0.,0.));
#955=AXIS2_PLACEMENT_3D('',#952,#953,#954);
#956=CIRCLE('',#955,4.);
#957=CARTESIAN_POINT('',(-8.0482778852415,0.,12.0482778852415));
#958=VERTEX_POINT('',#957);
#959=EDGE_CURVE('E186',#958,#958,#956,.T.);
#960=ORIENTED_EDGE('',*,*,#959,.T.);
#961=EDGE_LOOP('',(#960));
#962=FACE_BOUND('',#961,.T.);
#963=CARTESIAN_POINT('',(62.2630121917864,0.,27.7212790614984));
#964=DIRECTION('',(0.,1.,0.));
#965=DIRECTION('',(1.,0.,0.));
#966=AXIS2_PLACEMENT_3D('',#963,#964,#965);
#967=CIRCLE('',#966,4.);
#968=CARTESIAN_POINT('',(66.2630121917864,0.,27.7212790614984));
#969=VERTEX_POINT('',#968);
#970=EDGE_CURVE('E180',#969,#969,#967,.T.);
#971=ORIENTED_EDGE('',*,*,#970,.T.);
#972=EDGE_LOOP('',(#971));
#973=FACE_BOUND('',#972,.T.);
#974=CARTESIAN_POINT('',(43.0019479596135,0.,27.6356738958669));
#975=DIRECTION('',(0.,1.,0.));
#976=DIRECTION('',(1.,0.,0.));
#977=AXIS2_PLACEMENT_3D('',#974,#975,#976);
#978=CIRCLE('',#977,4.);
#979=CARTESIAN_POINT('',(47.0019479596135,0.,27.6356738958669));
#980=VERTEX_POINT('',#979);
#981=EDGE_CURVE('E174',#980,#980,#978,.T.);
#982=ORIENTED_EDGE('',*,*,#981,.T.);
#983=EDGE_LOOP('',(#982));
#984=FACE_BOUND('',#983,.T.);
#985=CARTESIAN_POINT('',(21.2470834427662,0.,26.6429999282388));
#986=DIRECTION('',(0.,1.,0.));
#987=DIRECTION('',(1.,0.,0.));
#988=AXIS2_PLACEMENT_3D('',#985,#986,#987);
#989=CIRCLE('',#988,4.);
#990=CARTESIAN_POINT('',(25.2470834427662,0.,26.6429999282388));
#991=VERTEX_POINT('',#990);
#992=EDGE_CURVE('E168',#991,#991,#989,.T.);
#993=ORIENTED_EDGE('',*,*,#992,.T.);
#994=EDGE_LOOP('',(#993));
#995=FACE_BOUND('',#994,.T.);
#996=CARTESIAN_POINT('',(0.,0.,17.0388379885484));
#997=DIRECTION('',(0.,1.,0.));
#998=DIRECTION('',(1.,0.,0.));
#999=AXIS2_PLACEMENT_3D('',#996,#997,#998);
#1000=CIRCLE('',#999,4.);
#1001=CARTESIAN_POINT('',(4.00000000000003,0.,17.0388379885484));
#1002=VERTEX_POINT('',#1001);
#1003=EDGE_CURVE('E162',#1002,#1002,#1000,.T.);
#1004=ORIENTED_EDGE('',*,*,#1003,.T.);
#1005=EDGE_LOOP('',(#1004));
#1006=FACE_BOUND('',#1005,.T.);
#1007=CARTESIAN_POINT('',(66.6659939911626,0.,14.1702944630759));
#1008=DIRECTION('',(0.,1.,0.));
#1009=DIRECTION('',(1.,0.,0.));
#1010=AXIS2_PLACEMENT_3D('',#1007,#1008,#1009);
#1011=CIRCLE('',#1010,4.);
#1012=CARTESIAN_POINT('',(70.6659939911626,0.,14.1702944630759));
#1013=VERTEX_POINT('',#1012);
#1014=EDGE_CURVE('E156',#1013,#1013,#1011,.T.);
#1015=ORIENTED_EDGE('',*,*,#1014,.T.);
#1016=EDGE_LOOP('',(#1015));
#1017=FACE_BOUND('',#1016,.T.);
#1018=CARTESIAN_POINT('',(49.0459359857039,0.,14.4011861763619));
#1019=DIRECTION('',(0.,1.,0.));
#1020=DIRECTION('',(1.,0.,0.));
#1021=AXIS2_PLACEMENT_3D('',#1018,#1019,#1020);
#1022=CIRCLE('',#1021,4.);
#1023=CARTESIAN_POINT('',(53.0459359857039,0.,14.4011861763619));
#1024=VERTEX_POINT('',#1023);
#1025=EDGE_CURVE('E150',#1024,#1024,#1022,.T.);
#1026=ORIENTED_EDGE('',*,*,#1025,.T.);
#1027=EDGE_LOOP('',(#1026));
#1028=FACE_BOUND('',#1027,.T.);
#1029=CARTESIAN_POINT('',(30.7029251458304,0.,14.7857494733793));
#1030=DIRECTION('',(0.,1.,0.));
#1031=DIRECTION('',(1.,0.,0.));
#1032=AXIS2_PLACEMENT_3D('',#1029,#1030,#1031);
#1033=CIRCLE('',#1032,4.);
#1034=CARTESIAN_POINT('',(34.7029251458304,0.,14.7857494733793));
#1035=VERTEX_POINT('',#1034);
#1036=EDGE_CURVE('E144',#1035,#1035,#1033,.T.);
#1037=ORIENTED_EDGE('',*,*,#1036,.T.);
#1038=EDGE_LOOP('',(#1037));
#1039=FACE_BOUND('',#1038,.T.);
#1040=CARTESIAN_POINT('',(12.0482778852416,0.,12.0482778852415));
#1041=DIRECTION('',(0.,1.,0.));
#1042=DIRECTION('',(1.,0.,0.));
#1043=AXIS2_PLACEMENT_3D('',#1040,#1041,#1042);
#1044=CIRCLE('',#1043,4.);
#1045=CARTESIAN_POINT('',(16.0482778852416,0.,12.0482778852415));
#1046=VERTEX_POINT('',#1045);
#1047=EDGE_CURVE('E138',#1046,#1046,#1044,.T.);
#1048=ORIENTED_EDGE('',*,*,#1047,.T.);
#1049=EDGE_LOOP('',(#1048));
#1050=FACE_BOUND('',#1049,.T.);
#1051=CARTESIAN_POINT('',(68.1553519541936,0.,0.));
#1052=DIRECTION('',(0.,1.,0.));
#1053=DIRECTION('',(1.,0.,0.));
#1054=AXIS2_PLACEMENT_3D('',#1051,#1052,#1053);
#1055=CIRCLE('',#1054,4.);
#1056=CARTESIAN_POINT('',(72.1553519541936,0.,0.));
#1057=VERTEX_POINT('',#1056);
#1058=EDGE_CURVE('E132',#1057,#1057,#1055,.T.);
#1059=ORIENTED_EDGE('',*,*,#1058,.T.);
#1060=EDGE_LOOP('',(#1059));
#1061=FACE_BOUND('',#1060,.T.);
#1062=CARTESIAN_POINT('',(51.1165139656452,0.,0.));
#1063=DIRECTION('',(0.,1.,0.));
#1064=DIRECTION('',(1.,0.,0.));
#1065=AXIS2_PLACEMENT_3D('',#1062,#1063,#1064);
#1066=CIRCLE('',#1065,4.);
#1067=CARTESIAN_POINT('',(55.1165139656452,0.,0.));
#1068=VERTEX_POINT('',#1067);
#1069=EDGE_CURVE('E126',#1068,#1068,#1066,.T.);
#1070=ORIENTED_EDGE('',*,*,#1069,.T.);
#1071=EDGE_LOOP('',(#1070));
#1072=FACE_BOUND('',#1071,.T.);
#1073=CARTESIAN_POINT('',(34.0776759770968,0.,0.));
#1074=DIRECTION('',(0.,1.,0.));
#1075=DIRECTION('',(1.,0.,0.));
#1076=AXIS2_PLACEMENT_3D('',#1073,#1074,#1075);
#1077=CIRCLE('',#1076,4.);
#1078=CARTESIAN_POINT('',(38.0776759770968,0.,0.));
#1079=VERTEX_POINT('',#1078);
#1080=EDGE_CURVE('E120',#1079,#1079,#1077,.T.);
#1081=ORIENTED_EDGE('',*,*,#1080,.T.);
#1082=EDGE_LOOP('',(#1081));
#1083=FACE_BOUND('',#1082,.T.);
#1084=CARTESIAN_POINT('',(17.0388379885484,0.,0.));
#1085=DIRECTION('',(0.,1.,0.));
#1086=DIRECTION('',(1.,0.,0.));
#1087=AXIS2_PLACEMENT_3D('',#1084,#1085,#1086);
#1088=CIRCLE('',#1087,4.);
#1089=CARTESIAN_POINT('',(21.0388379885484,0.,0.));
#1090=VERTEX_POINT('',#1089);
#1091=EDGE_CURVE('E114',#1090,#1090,#1088,.T.);
#1092=ORIENTED_EDGE('',*,*,#1091,.T.);
#1093=EDGE_LOOP('',(#1092));
#1094=FACE_BOUND('',#1093,.T.);
#1095=CARTESIAN_POINT('',(0.,0.,0.));
#1096=DIRECTION('',(0.,1.,0.));
#1097=DIRECTION('',(1.,0.,0.));
#1098=AXIS2_PLACEMENT_3D('',#1095,#1096,#1097);
#1099=CIRCLE('',#1098,4.);
#1100=CARTESIAN_POINT('',(4.00000000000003,0.,0.));
#1101=VERTEX_POINT('',#1100);
#1102=EDGE_CURVE('E100',#1101,#1101,#1099,.T.);
#1103=ORIENTED_EDGE('',*,*,#1102,.T.);
#1104=EDGE_LOOP('',(#1103));
#1105=FACE_BOUND('',#1104,.T.);
#1106=ORIENTED_EDGE('',*,*,#32,.F.);
#1107=ORIENTED_EDGE('',*,*,#130,.F.);
#1108=ORIENTED_EDGE('',*,*,#101,.F.);
#1109=ORIENTED_EDGE('',*,*,#70,.F.);
#1110=EDGE_LOOP('',(#1106,#1107,#1108,#1109));
#1111=FACE_BOUND('',#1110,.T.);
#1112=ADVANCED_FACE('F108',(#643,#654,#665,#676,#687,#698,#709,#720,#731,#742,#753,#764,#775,
#786,#797,#808,#819,#830,#841,#852,#863,#874,#885,#896,#907,#918,#929,#940,#951,#962,#973,#984,
#995,#1006,#1017,#1028,#1039,#1050,#1061,#1072,#1083,#1094,#1105,#1111),#632,.F.);
#1113=CARTESIAN_POINT('',(0.,0.,0.));
#1114=DIRECTION('',(0.,1.,0.));
#1115=DIRECTION('',(0.,0.,1.));
#1116=AXIS2_PLACEMENT_3D('',#1113,#1114,#1115);
#1117=CYLINDRICAL_SURFACE('',#1116,4.);
#1118=ORIENTED_EDGE('',*,*,#1102,.F.);
#1119=EDGE_LOOP('',(#1118));
#1120=FACE_BOUND('',#1119,.T.);
#1121=ORIENTED_EDGE('',*,*,#617,.T.);
#1122=EDGE_LOOP('',(#1121));
#1123=FACE_BOUND('',#1122,.T.);
#1124=ADVANCED_FACE('F465',(#1120,#1123),#1117,.F.);
#1125=CARTESIAN_POINT('',(17.0388379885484,0.,0.));
#1126=DIRECTION('',(0.,1.,0.));
#1127=DIRECTION('',(0.,0.,1.));
#1128=AXIS2_PLACEMENT_3D('',#1125,#1126,#1127);
#1129=CYLINDRICAL_SURFACE('',#1128,4.);
#1130=ORIENTED_EDGE('',*,*,#1091,.F.);
#1131=EDGE_LOOP('',(#1130));
#1132=FACE_BOUND('',#1131,.T.);
#1133=ORIENTED_EDGE('',*,*,#606,.T.);
#1134=EDGE_LOOP('',(#1133));
#1135=FACE_BOUND('',#1134,.T.);
#1136=ADVANCED_FACE('F467',(#1132,#1135),#1129,.F.);
#1137=CARTESIAN_POINT('',(34.0776759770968,0.,0.));
#1138=DIRECTION('',(0.,1.,0.));
#1139=DIRECTION('',(0.,0.,1.));
#1140=AXIS2_PLACEMENT_3D('',#1137,#1138,#1139);
#1141=CYLINDRICAL_SURFACE('',#1140,4.);
#1142=ORIENTED_EDGE('',*,*,#1080,.F.);
#1143=EDGE_LOOP('',(#1142));
#1144=FACE_BOUND('',#1143,.T.);
#1145=ORIENTED_EDGE('',*,*,#595,.T.);
#1146=EDGE_LOOP('',(#1145));
#1147=FACE_BOUND('',#1146,.T.);
#1148=ADVANCED_FACE('F474',(#1144,#1147),#1141,.F.);
#1149=CARTESIAN_POINT('',(51.1165139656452,0.,0.));
#1150=DIRECTION('',(0.,1.,0.));
#1151=DIRECTION('',(0.,0.,1.));
#1152=AXIS2_PLACEMENT_3D('',#1149,#1150,#1151);
#1153=CYLINDRICAL_SURFACE('',#1152,4.);
#1154=ORIENTED_EDGE('',*,*,#1069,.F.);
#1155=EDGE_LOOP('',(#1154));
#1156=FACE_BOUND('',#1155,.T.);
#1157=ORIENTED_EDGE('',*,*,#584,.T.);
#1158=EDGE_LOOP('',(#1157));
#1159=FACE_BOUND('',#1158,.T.);
#1160=ADVANCED_FACE('F520',(#1156,#1159),#1153,.F.);
#1161=CARTESIAN_POINT('',(68.1553519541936,0.,0.));
#1162=DIRECTION('',(0.,1.,0.));
#1163=DIRECTION('',(0.,0.,1.));
#1164=AXIS2_PLACEMENT_3D('',#1161,#1162,#1163);
#1165=CYLINDRICAL_SURFACE('',#1164,4.);
#1166=ORIENTED_EDGE('',*,*,#1058,.F.);
#1167=EDGE_LOOP('',(#1166));
#1168=FACE_BOUND('',#1167,.T.);
#1169=ORIENTED_EDGE('',*,*,#573,.T.);
#1170=EDGE_LOOP('',(#1169));
#1171=FACE_BOUND('',#1170,.T.);
#1172=ADVANCED_FACE('F530',(#1168,#1171),#1165,.F.);
#1173=CARTESIAN_POINT('',(12.0482778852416,0.,12.0482778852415));
#1174=DIRECTION('',(0.,1.,0.));
#1175=DIRECTION('',(0.,0.,1.));
#1176=AXIS2_PLACEMENT_3D('',#1173,#1174,#1175);
#1177=CYLINDRICAL_SURFACE('',#1176,4.);
#1178=ORIENTED_EDGE('',*,*,#1047,.F.);
#1179=EDGE_LOOP('',(#1178));
#1180=FACE_BOUND('',#1179,.T.);
#1181=ORIENTED_EDGE('',*,*,#562,.T.);
#1182=EDGE_LOOP('',(#1181));
#1183=FACE_BOUND('',#1182,.T.);
#1184=ADVANCED_FACE('F540',(#1180,#1183),#1177,.F.);
#1185=CARTESIAN_POINT('',(30.7029251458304,0.,14.7857494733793));
#1186=DIRECTION('',(0.,1.,0.));
#1187=DIRECTION('',(0.,0.,1.));
#1188=AXIS2_PLACEMENT_3D('',#1185,#1186,#1187);
#1189=CYLINDRICAL_SURFACE('',#1188,4.);
#1190=ORIENTED_EDGE('',*,*,#1036,.F.);
#1191=EDGE_LOOP('',(#1190));
#1192=FACE_BOUND('',#1191,.T.);
#1193=ORIENTED_EDGE('',*,*,#551,.T.);
#1194=EDGE_LOOP('',(#1193));
#1195=FACE_BOUND('',#1194,.T.);
#1196=ADVANCED_FACE('F550',(#1192,#1195),#1189,.F.);
#1197=CARTESIAN_POINT('',(49.0459359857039,0.,14.4011861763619));
#1198=DIRECTION('',(0.,1.,0.));
#1199=DIRECTION('',(0.,0.,1.));
#1200=AXIS2_PLACEMENT_3D('',#1197,#1198,#1199);
#1201=CYLINDRICAL_SURFACE('',#1200,4.);
#1202=ORIENTED_EDGE('',*,*,#1025,.F.);
#1203=EDGE_LOOP('',(#1202));
#1204=FACE_BOUND('',#1203,.T.);
#1205=ORIENTED_EDGE('',*,*,#540,.T.);
#1206=EDGE_LOOP('',(#1205));
#1207=FACE_BOUND('',#1206,.T.);
#1208=ADVANCED_FACE('F560',(#1204,#1207),#1201,.F.);
#1209=CARTESIAN_POINT('',(66.6659939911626,0.,14.1702944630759));
#1210=DIRECTION('',(0.,1.,0.));
#1211=DIRECTION('',(0.,0.,1.));
#1212=AXIS2_PLACEMENT_3D('',#1209,#1210,#1211);
#1213=CYLINDRICAL_SURFACE('',#1212,4.);
#1214=ORIENTED_EDGE('',*,*,#1014,.F.);
#1215=EDGE_LOOP('',(#1214));
#1216=FACE_BOUND('',#1215,.T.);
#1217=ORIENTED_EDGE('',*,*,#529,.T.);
#1218=EDGE_LOOP('',(#1217));
#1219=FACE_BOUND('',#1218,.T.);
#1220=ADVANCED_FACE('F570',(#1216,#1219),#1213,.F.);
#1221=CARTESIAN_POINT('',(0.,0.,17.0388379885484));
#1222=DIRECTION('',(0.,1.,0.));
#1223=DIRECTION('',(0.,0.,1.));
#1224=AXIS2_PLACEMENT_3D('',#1221,#1222,#1223);
#1225=CYLINDRICAL_SURFACE('',#1224,4.);
#1226=ORIENTED_EDGE('',*,*,#1003,.F.);
#1227=EDGE_LOOP('',(#1226));
#1228=FACE_BOUND('',#1227,.T.);
#1229=ORIENTED_EDGE('',*,*,#518,.T.);
#1230=EDGE_LOOP('',(#1229));
#1231=FACE_BOUND('',#1230,.T.);
#1232=ADVANCED_FACE('F580',(#1228,#1231),#1225,.F.);
#1233=CARTESIAN_POINT('',(21.2470834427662,0.,26.6429999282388));
#1234=DIRECTION('',(0.,1.,0.));
#1235=DIRECTION('',(0.,0.,1.));
#1236=AXIS2_PLACEMENT_3D('',#1233,#1234,#1235);
#1237=CYLINDRICAL_SURFACE('',#1236,4.);
#1238=ORIENTED_EDGE('',*,*,#992,.F.);
#1239=EDGE_LOOP('',(#1238));
#1240=FACE_BOUND('',#1239,.T.);
#1241=ORIENTED_EDGE('',*,*,#507,.T.);
#1242=EDGE_LOOP('',(#1241));
#1243=FACE_BOUND('',#1242,.T.);
#1244=ADVANCED_FACE('F590',(#1240,#1243),#1237,.F.);
#1245=CARTESIAN_POINT('',(43.0019479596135,0.,27.6356738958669));
#1246=DIRECTION('',(0.,1.,0.));
#1247=DIRECTION('',(0.,0.,1.));
#1248=AXIS2_PLACEMENT_3D('',#1245,#1246,#1247);
#1249=CYLINDRICAL_SURFACE('',#1248,4.);
#1250=ORIENTED_EDGE('',*,*,#981,.F.);
#1251=EDGE_LOOP('',(#1250));
#1252=FACE_BOUND('',#1251,.T.);
#1253=ORIENTED_EDGE('',*,*,#496,.T.);
#1254=EDGE_LOOP('',(#1253));
#1255=FACE_BOUND('',#1254,.T.);
#1256=ADVANCED_FACE('F600',(#1252,#1255),#1249,.F.);
#1257=CARTESIAN_POINT('',(62.2630121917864,0.,27.7212790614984));
#1258=DIRECTION('',(0.,1.,0.));
#1259=DIRECTION('',(0.,0.,1.));
#1260=AXIS2_PLACEMENT_3D('',#1257,#1258,#1259);
#1261=CYLINDRICAL_SURFACE('',#1260,4.);
#1262=ORIENTED_EDGE('',*,*,#970,.F.);
#1263=EDGE_LOOP('',(#1262));
#1264=FACE_BOUND('',#1263,.T.);
#1265=ORIENTED_EDGE('',*,*,#485,.T.);
#1266=EDGE_LOOP('',(#1265));
#1267=FACE_BOUND('',#1266,.T.);
#1268=ADVANCED_FACE('F610',(#1264,#1267),#1261,.F.);
#1269=CARTESIAN_POINT('',(-12.0482778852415,0.,12.0482778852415));
#1270=DIRECTION('',(0.,1.,0.));
#1271=DIRECTION('',(0.,0.,1.));
#1272=AXIS2_PLACEMENT_3D('',#1269,#1270,#1271);
#1273=CYLINDRICAL_SURFACE('',#1272,4.);
#1274=ORIENTED_EDGE('',*,*,#959,.F.);
#1275=EDGE_LOOP('',(#1274));
#1276=FACE_BOUND('',#1275,.T.);
#1277=ORIENTED_EDGE('',*,*,#474,.T.);
#1278=EDGE_LOOP('',(#1277));
#1279=FACE_BOUND('',#1278,.T.);
#1280=ADVANCED_FACE('F620',(#1276,#1279),#1273,.F.);
#1281=CARTESIAN_POINT('',(7.58299628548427,0.,33.2232774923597));
#1282=DIRECTION('',(0.,1.,0.));
#1283=DIRECTION('',(0.,0.,1.));
#1284=AXIS2_PLACEMENT_3D('',#1281,#1282,#1283);
#1285=CYLINDRICAL_SURFACE('',#1284,4.);
#1286=ORIENTED_EDGE('',*,*,#948,.F.);
#1287=EDGE_LOOP('',(#1286));
#1288=FACE_BOUND('',#1287,.T.);
#1289=ORIENTED_EDGE('',*,*,#463,.T.);
#1290=EDGE_LOOP('',(#1289));
#1291=FACE_BOUND('',#1290,.T.);
#1292=ADVANCED_FACE('F630',(#1288,#1291),#1285,.F.);
#1293=CARTESIAN_POINT('',(-17.0388379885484,0.,0.));
#1294=DIRECTION('',(0.,1.,0.));
#1295=DIRECTION('',(0.,0.,1.));
#1296=AXIS2_PLACEMENT_3D('',#1293,#1294,#1295);
#1297=CYLINDRICAL_SURFACE('',#1296,4.);
#1298=ORIENTED_EDGE('',*,*,#937,.F.);
#1299=EDGE_LOOP('',(#1298));
#1300=FACE_BOUND('',#1299,.T.);
#1301=ORIENTED_EDGE('',*,*,#452,.T.);
#1302=EDGE_LOOP('',(#1301));
#1303=FACE_BOUND('',#1302,.T.);
#1304=ADVANCED_FACE('F640',(#1300,#1303),#1297,.F.);
#1305=CARTESIAN_POINT('',(-7.58299628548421,0.,33.2232774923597));
#1306=DIRECTION('',(0.,1.,0.));
#1307=DIRECTION('',(0.,0.,1.));
#1308=AXIS2_PLACEMENT_3D('',#1305,#1306,#1307);
#1309=CYLINDRICAL_SURFACE('',#1308,4.);
#1310=ORIENTED_EDGE('',*,*,#926,.F.);
#1311=EDGE_LOOP('',(#1310));
#1312=FACE_BOUND('',#1311,.T.);
#1313=ORIENTED_EDGE('',*,*,#441,.T.);
#1314=EDGE_LOOP('',(#1313));
#1315=FACE_BOUND('',#1314,.T.);
#1316=ADVANCED_FACE('F650',(#1312,#1315),#1309,.F.);
#1317=CARTESIAN_POINT('',(-12.0482778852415,0.,-12.0482778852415));
#1318=DIRECTION('',(0.,1.,0.));
#1319=DIRECTION('',(0.,0.,1.));
#1320=AXIS2_PLACEMENT_3D('',#1317,#1318,#1319);
#1321=CYLINDRICAL_SURFACE('',#1320,4.);
#1322=ORIENTED_EDGE('',*,*,#915,.F.);
#1323=EDGE_LOOP('',(#1322));
#1324=FACE_BOUND('',#1323,.T.);
#1325=ORIENTED_EDGE('',*,*,#430,.T.);
#1326=EDGE_LOOP('',(#1325));
#1327=FACE_BOUND('',#1326,.T.);
#1328=ADVANCED_FACE('F660',(#1324,#1327),#1321,.F.);
#1329=CARTESIAN_POINT('',(-21.2470834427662,0.,26.6429999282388));
#1330=DIRECTION('',(0.,1.,0.));
#1331=DIRECTION('',(0.,0.,1.));
#1332=AXIS2_PLACEMENT_3D('',#1329,#1330,#1331);
#1333=CYLINDRICAL_SURFACE('',#1332,4.);
#1334=ORIENTED_EDGE('',*,*,#904,.F.);
#1335=EDGE_LOOP('',(#1334));
#1336=FACE_BOUND('',#1335,.T.);
#1337=ORIENTED_EDGE('',*,*,#419,.T.);
#1338=EDGE_LOOP('',(#1337));
#1339=FACE_BOUND('',#1338,.T.);
#1340=ADVANCED_FACE('F670',(#1336,#1339),#1333,.F.);
#1341=CARTESIAN_POINT('',(0.,0.,-17.0388379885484));
#1342=DIRECTION('',(0.,1.,0.));
#1343=DIRECTION('',(0.,0.,1.));
#1344=AXIS2_PLACEMENT_3D('',#1341,#1342,#1343);
#1345=CYLINDRICAL_SURFACE('',#1344,4.);
#1346=ORIENTED_EDGE('',*,*,#893,.F.);
#1347=EDGE_LOOP('',(#1346));
#1348=FACE_BOUND('',#1347,.T.);
#1349=ORIENTED_EDGE('',*,*,#408,.T.);
#1350=EDGE_LOOP('',(#1349));
#1351=FACE_BOUND('',#1350,.T.);
#1352=ADVANCED_FACE('F680',(#1348,#1351),#1345,.F.);
#1353=CARTESIAN_POINT('',(-30.7029251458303,0.,14.7857494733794));
#1354=DIRECTION('',(0.,1.,0.));
#1355=DIRECTION('',(0.,0.,1.));
#1356=AXIS2_PLACEMENT_3D('',#1353,#1354,#1355);
#1357=CYLINDRICAL_SURFACE('',#1356,4.);
#1358=ORIENTED_EDGE('',*,*,#882,.F.);
#1359=EDGE_LOOP('',(#1358));
#1360=FACE_BOUND('',#1359,.T.);
#1361=ORIENTED_EDGE('',*,*,#397,.T.);
#1362=EDGE_LOOP('',(#1361));
#1363=FACE_BOUND('',#1362,.T.);
#1364=ADVANCED_FACE('F690',(#1360,#1363),#1357,.F.);
#1365=CARTESIAN_POINT('',(12.0482778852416,0.,-12.0482778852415));
#1366=DIRECTION('',(0.,1.,0.));
#1367=DIRECTION('',(0.,0.,1.));
#1368=AXIS2_PLACEMENT_3D('',#1365,#1366,#1367);
#1369=CYLINDRICAL_SURFACE('',#1368,4.);
#1370=ORIENTED_EDGE('',*,*,#871,.F.);
#1371=EDGE_LOOP('',(#1370));
#1372=FACE_BOUND('',#1371,.T.);
#1373=ORIENTED_EDGE('',*,*,#386,.T.);
#1374=EDGE_LOOP('',(#1373));
#1375=FACE_BOUND('',#1374,.T.);
#1376=ADVANCED_FACE('F700',(#1372,#1375),#1369,.F.);
#1377=CARTESIAN_POINT('',(-34.0776759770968,0.,0.));
#1378=DIRECTION('',(0.,1.,0.));
#1379=DIRECTION('',(0.,0.,1.));
#1380=AXIS2_PLACEMENT_3D('',#1377,#1378,#1379);
#1381=CYLINDRICAL_SURFACE('',#1380,4.);
#1382=ORIENTED_EDGE('',*,*,#860,.F.);
#1383=EDGE_LOOP('',(#1382));
#1384=FACE_BOUND('',#1383,.T.);
#1385=ORIENTED_EDGE('',*,*,#375,.T.);
#1386=EDGE_LOOP('',(#1385));
#1387=FACE_BOUND('',#1386,.T.);
#1388=ADVANCED_FACE('F710',(#1384,#1387),#1381,.F.);
#1389=CARTESIAN_POINT('',(-30.7029251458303,0.,-14.7857494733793));
#1390=DIRECTION('',(0.,1.,0.));
#1391=DIRECTION('',(0.,0.,1.));
#1392=AXIS2_PLACEMENT_3D('',#1389,#1390,#1391);
#1393=CYLINDRICAL_SURFACE('',#1392,4.);
#1394=ORIENTED_EDGE('',*,*,#849,.F.);
#1395=EDGE_LOOP('',(#1394));
#1396=FACE_BOUND('',#1395,.T.);
#1397=ORIENTED_EDGE('',*,*,#364,.T.);
#1398=EDGE_LOOP('',(#1397));
#1399=FACE_BOUND('',#1398,.T.);
#1400=ADVANCED_FACE('F720',(#1396,#1399),#1393,.F.);
#1401=CARTESIAN_POINT('',(-21.2470834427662,0.,-26.6429999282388));
#1402=DIRECTION('',(0.,1.,0.));
#1403=DIRECTION('',(0.,0.,1.));
#1404=AXIS2_PLACEMENT_3D('',#1401,#1402,#1403);
#1405=CYLINDRICAL_SURFACE('',#1404,4.);
#1406=ORIENTED_EDGE('',*,*,#838,.F.);
#1407=EDGE_LOOP('',(#1406));
#1408=FACE_BOUND('',#1407,.T.);
#1409=ORIENTED_EDGE('',*,*,#353,.T.);
#1410=EDGE_LOOP('',(#1409));
#1411=FACE_BOUND('',#1410,.T.);
#1412=ADVANCED_FACE('F730',(#1408,#1411),#1405,.F.);
#1413=CARTESIAN_POINT('',(-43.0019479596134,0.,27.6356738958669));
#1414=DIRECTION('',(0.,1.,0.));
#1415=DIRECTION('',(0.,0.,1.));
#1416=AXIS2_PLACEMENT_3D('',#1413,#1414,#1415);
#1417=CYLINDRICAL_SURFACE('',#1416,4.);
#1418=ORIENTED_EDGE('',*,*,#827,.F.);
#1419=EDGE_LOOP('',(#1418));
#1420=FACE_BOUND('',#1419,.T.);
#1421=ORIENTED_EDGE('',*,*,#342,.T.);
#1422=EDGE_LOOP('',(#1421));
#1423=FACE_BOUND('',#1422,.T.);
#1424=ADVANCED_FACE('F740',(#1420,#1423),#1417,.F.);
#1425=CARTESIAN_POINT('',(-7.58299628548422,0.,-33.2232774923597));
#1426=DIRECTION('',(0.,1.,0.));
#1427=DIRECTION('',(0.,0.,1.));
#1428=AXIS2_PLACEMENT_3D('',#1425,#1426,#1427);
#1429=CYLINDRICAL_SURFACE('',#1428,4.);
#1430=ORIENTED_EDGE('',*,*,#816,.F.);
#1431=EDGE_LOOP('',(#1430));
#1432=FACE_BOUND('',#1431,.T.);
#1433=ORIENTED_EDGE('',*,*,#331,.T.);
#1434=EDGE_LOOP('',(#1433));
#1435=FACE_BOUND('',#1434,.T.);
#1436=ADVANCED_FACE('F750',(#1432,#1435),#1429,.F.);
#1437=CARTESIAN_POINT('',(-49.0459359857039,0.,14.4011861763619));
#1438=DIRECTION('',(0.,1.,0.));
#1439=DIRECTION('',(0.,0.,1.));
#1440=AXIS2_PLACEMENT_3D('',#1437,#1438,#1439);
#1441=CYLINDRICAL_SURFACE('',#1440,4.);
#1442=ORIENTED_EDGE('',*,*,#805,.F.);
#1443=EDGE_LOOP('',(#1442));
#1444=FACE_BOUND('',#1443,.T.);
#1445=ORIENTED_EDGE('',*,*,#320,.T.);
#1446=EDGE_LOOP('',(#1445));
#1447=FACE_BOUND('',#1446,.T.);
#1448=ADVANCED_FACE('F760',(#1444,#1447),#1441,.F.);
#1449=CARTESIAN_POINT('',(7.58299628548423,0.,-33.2232774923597));
#1450=DIRECTION('',(0.,1.,0.));
#1451=DIRECTION('',(0.,0.,1.));
#1452=AXIS2_PLACEMENT_3D('',#1449,#1450,#1451);
#1453=CYLINDRICAL_SURFACE('',#1452,4.);
#1454=ORIENTED_EDGE('',*,*,#794,.F.);
#1455=EDGE_LOOP('',(#1454));
#1456=FACE_BOUND('',#1455,.T.);
#1457=ORIENTED_EDGE('',*,*,#309,.T.);
#1458=EDGE_LOOP('',(#1457));
#1459=FACE_BOUND('',#1458,.T.);
#1460=ADVANCED_FACE('F770',(#1456,#1459),#1453,.F.);
#1461=CARTESIAN_POINT('',(-51.1165139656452,0.,0.));
#1462=DIRECTION('',(0.,1.,0.));
#1463=DIRECTION('',(0.,0.,1.));
#1464=AXIS2_PLACEMENT_3D('',#1461,#1462,#1463);
#1465=CYLINDRICAL_SURFACE('',#1464,4.);
#1466=ORIENTED_EDGE('',*,*,#783,.F.);
#1467=EDGE_LOOP('',(#1466));
#1468=FACE_BOUND('',#1467,.T.);
#1469=ORIENTED_EDGE('',*,*,#298,.T.);
#1470=EDGE_LOOP('',(#1469));
#1471=FACE_BOUND('',#1470,.T.);
#1472=ADVANCED_FACE('F780',(#1468,#1471),#1465,.F.);
#1473=CARTESIAN_POINT('',(21.2470834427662,0.,-26.6429999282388));
#1474=DIRECTION('',(0.,1.,0.));
#1475=DIRECTION('',(0.,0.,1.));
#1476=AXIS2_PLACEMENT_3D('',#1473,#1474,#1475);
#1477=CYLINDRICAL_SURFACE('',#1476,4.);
#1478=ORIENTED_EDGE('',*,*,#772,.F.);
#1479=EDGE_LOOP('',(#1478));
#1480=FACE_BOUND('',#1479,.T.);
#1481=ORIENTED_EDGE('',*,*,#287,.T.);
#1482=EDGE_LOOP('',(#1481));
#1483=FACE_BOUND('',#1482,.T.);
#1484=ADVANCED_FACE('F790',(#1480,#1483),#1477,.F.);
#1485=CARTESIAN_POINT('',(-49.0459359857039,0.,-14.4011861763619));
#1486=DIRECTION('',(0.,1.,0.));
#1487=DIRECTION('',(0.,0.,1.));
#1488=AXIS2_PLACEMENT_3D('',#1485,#1486,#1487);
#1489=CYLINDRICAL_SURFACE('',#1488,4.);
#1490=ORIENTED_EDGE('',*,*,#761,.F.);
#1491=EDGE_LOOP('',(#1490));
#1492=FACE_BOUND('',#1491,.T.);
#1493=ORIENTED_EDGE('',*,*,#276,.T.);
#1494=EDGE_LOOP('',(#1493));
#1495=FACE_BOUND('',#1494,.T.);
#1496=ADVANCED_FACE('F800',(#1492,#1495),#1489,.F.);
#1497=CARTESIAN_POINT('',(30.7029251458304,0.,-14.7857494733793));
#1498=DIRECTION('',(0.,1.,0.));
#1499=DIRECTION('',(0.,0.,1.));
#1500=AXIS2_PLACEMENT_3D('',#1497,#1498,#1499);
#1501=CYLINDRICAL_SURFACE('',#1500,4.);
#1502=ORIENTED_EDGE('',*,*,#750,.F.);
#1503=EDGE_LOOP('',(#1502));
#1504=FACE_BOUND('',#1503,.T.);
#1505=ORIENTED_EDGE('',*,*,#265,.T.);
#1506=EDGE_LOOP('',(#1505));
#1507=FACE_BOUND('',#1506,.T.);
#1508=ADVANCED_FACE('F810',(#1504,#1507),#1501,.F.);
#1509=CARTESIAN_POINT('',(-43.0019479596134,0.,-27.6356738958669));
#1510=DIRECTION('',(0.,1.,0.));
#1511=DIRECTION('',(0.,0.,1.));
#1512=AXIS2_PLACEMENT_3D('',#1509,#1510,#1511);
#1513=CYLINDRICAL_SURFACE('',#1512,4.);
#1514=ORIENTED_EDGE('',*,*,#739,.F.);
#1515=EDGE_LOOP('',(#1514));
#1516=FACE_BOUND('',#1515,.T.);
#1517=ORIENTED_EDGE('',*,*,#254,.T.);
#1518=EDGE_LOOP('',(#1517));
#1519=FACE_BOUND('',#1518,.T.);
#1520=ADVANCED_FACE('F820',(#1516,#1519),#1513,.F.);
#1521=CARTESIAN_POINT('',(-62.2630121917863,0.,27.7212790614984));
#1522=DIRECTION('',(0.,1.,0.));
#1523=DIRECTION('',(0.,0.,1.));
#1524=AXIS2_PLACEMENT_3D('',#1521,#1522,#1523);
#1525=CYLINDRICAL_SURFACE('',#1524,4.);
#1526=ORIENTED_EDGE('',*,*,#728,.F.);
#1527=EDGE_LOOP('',(#1526));
#1528=FACE_BOUND('',#1527,.T.);
#1529=ORIENTED_EDGE('',*,*,#243,.T.);
#1530=EDGE_LOOP('',(#1529));
#1531=FACE_BOUND('',#1530,.T.);
#1532=ADVANCED_FACE('F830',(#1528,#1531),#1525,.F.);
#1533=CARTESIAN_POINT('',(-66.6659939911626,0.,14.1702944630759));
#1534=DIRECTION('',(0.,1.,0.));
#1535=DIRECTION('',(0.,0.,1.));
#1536=AXIS2_PLACEMENT_3D('',#1533,#1534,#1535);
#1537=CYLINDRICAL_SURFACE('',#1536,4.);
#1538=ORIENTED_EDGE('',*,*,#717,.F.);
#1539=EDGE_LOOP('',(#1538));
#1540=FACE_BOUND('',#1539,.T.);
#1541=ORIENTED_EDGE('',*,*,#232,.T.);
#1542=EDGE_LOOP('',(#1541));
#1543=FACE_BOUND('',#1542,.T.);
#1544=ADVANCED_FACE('F840',(#1540,#1543),#1537,.F.);
#1545=CARTESIAN_POINT('',(-68.1553519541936,0.,0.));
#1546=DIRECTION('',(0.,1.,0.));
#1547=DIRECTION('',(0.,0.,1.));
#1548=AXIS2_PLACEMENT_3D('',#1545,#1546,#1547);
#1549=CYLINDRICAL_SURFACE('',#1548,4.);
#1550=ORIENTED_EDGE('',*,*,#706,.F.);
#1551=EDGE_LOOP('',(#1550));
#1552=FACE_BOUND('',#1551,.T.);
#1553=ORIENTED_EDGE('',*,*,#221,.T.);
#1554=EDGE_LOOP('',(#1553));
#1555=FACE_BOUND('',#1554,.T.);
#1556=ADVANCED_FACE('F850',(#1552,#1555),#1549,.F.);
#1557=CARTESIAN_POINT('',(-66.6659939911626,0.,-14.1702944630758));
#1558=DIRECTION('',(0.,1.,0.));
#1559=DIRECTION('',(0.,0.,1.));
#1560=AXIS2_PLACEMENT_3D('',#1557,#1558,#1559);
#1561=CYLINDRICAL_SURFACE('',#1560,4.);
#1562=ORIENTED_EDGE('',*,*,#695,.F.);
#1563=EDGE_LOOP('',(#1562));
#1564=FACE_BOUND('',#1563,.T.);
#1565=ORIENTED_EDGE('',*,*,#210,.T.);
#1566=EDGE_LOOP('',(#1565));
#1567=FACE_BOUND('',#1566,.T.);
#1568=ADVANCED_FACE('F860',(#1564,#1567),#1561,.F.);
#1569=CARTESIAN_POINT('',(-62.2630121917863,0.,-27.7212790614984));
#1570=DIRECTION('',(0.,1.,0.));
#1571=DIRECTION('',(0.,0.,1.));
#1572=AXIS2_PLACEMENT_3D('',#1569,#1570,#1571);
#1573=CYLINDRICAL_SURFACE('',#1572,4.);
#1574=ORIENTED_EDGE('',*,*,#684,.F.);
#1575=EDGE_LOOP('',(#1574));
#1576=FACE_BOUND('',#1575,.T.);
#1577=ORIENTED_EDGE('',*,*,#199,.T.);
#1578=EDGE_LOOP('',(#1577));
#1579=FACE_BOUND('',#1578,.T.);
#1580=ADVANCED_FACE('F870',(#1576,#1579),#1573,.F.);
#1581=CARTESIAN_POINT('',(43.0019479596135,0.,-27.6356738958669));
#1582=DIRECTION('',(0.,1.,0.));
#1583=DIRECTION('',(0.,0.,1.));
#1584=AXIS2_PLACEMENT_3D('',#1581,#1582,#1583);
#1585=CYLINDRICAL_SURFACE('',#1584,4.);
#1586=ORIENTED_EDGE('',*,*,#673,.F.);
#1587=EDGE_LOOP('',(#1586));
#1588=FACE_BOUND('',#1587,.T.);
#1589=ORIENTED_EDGE('',*,*,#188,.T.);
#1590=EDGE_LOOP('',(#1589));
#1591=FACE_BOUND('',#1590,.T.);
#1592=ADVANCED_FACE('F880',(#1588,#1591),#1585,.F.);
#1593=CARTESIAN_POINT('',(49.0459359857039,0.,-14.4011861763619));
#1594=DIRECTION('',(0.,1.,0.));
#1595=DIRECTION('',(0.,0.,1.));
#1596=AXIS2_PLACEMENT_3D('',#1593,#1594,#1595);
#1597=CYLINDRICAL_SURFACE('',#1596,4.);
#1598=ORIENTED_EDGE('',*,*,#662,.F.);
#1599=EDGE_LOOP('',(#1598));
#1600=FACE_BOUND('',#1599,.T.);
#1601=ORIENTED_EDGE('',*,*,#177,.T.);
#1602=EDGE_LOOP('',(#1601));
#1603=FACE_BOUND('',#1602,.T.);
#1604=ADVANCED_FACE('F890',(#1600,#1603),#1597,.F.);
#1605=CARTESIAN_POINT('',(62.2630121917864,0.,-27.7212790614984));
#1606=DIRECTION('',(0.,1.,0.));
#1607=DIRECTION('',(0.,0.,1.));
#1608=AXIS2_PLACEMENT_3D('',#1605,#1606,#1607);
#1609=CYLINDRICAL_SURFACE('',#1608,4.);
#1610=ORIENTED_EDGE('',*,*,#651,.F.);
#1611=EDGE_LOOP('',(#1610));
#1612=FACE_BOUND('',#1611,.T.);
#1613=ORIENTED_EDGE('',*,*,#166,.T.);
#1614=EDGE_LOOP('',(#1613));
#1615=FACE_BOUND('',#1614,.T.);
#1616=ADVANCED_FACE('F374',(#1612,#1615),#1609,.F.);
#1617=CARTESIAN_POINT('',(66.6659939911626,0.,-14.1702944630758));
#1618=DIRECTION('',(0.,1.,0.));
#1619=DIRECTION('',(0.,0.,1.));
#1620=AXIS2_PLACEMENT_3D('',#1617,#1618,#1619);
#1621=CYLINDRICAL_SURFACE('',#1620,4.);
#1622=ORIENTED_EDGE('',*,*,#640,.F.);
#1623=EDGE_LOOP('',(#1622));
#1624=FACE_BOUND('',#1623,.T.);
#1625=ORIENTED_EDGE('',*,*,#155,.T.);
#1626=EDGE_LOOP('',(#1625));
#1627=FACE_BOUND('',#1626,.T.);
#1628=ADVANCED_FACE('F371',(#1624,#1627),#1621,.F.);
#1629=CLOSED_SHELL('',(#58,#89,#120,#142,#627,#1112,#1124,#1136,#1148,#1160,#1172,#1184,#1196,
#1208,#1220,#1232,#1244,#1256,#1268,#1280,#1292,#1304,#1316,#1328,#1340,#1352,#1364,#1376,#1388,
#1400,#1412,#1424,#1436,#1448,#1460,#1472,#1484,#1496,#1508,#1520,#1532,#1544,#1556,#1568,#1580,
#1592,#1604,#1616,#1628));
#1630=MANIFOLD_SOLID_BREP('B2',#1629);
#1631=ADVANCED_BREP_SHAPE_REPRESENTATION('',(#18,#1630),#14);
#1632=SHAPE_DEFINITION_REPRESENTATION(#9,#1631);
ENDSEC;
END-ISO-10303-21;
